VERSION 5.8 ;
BUSBITCHARS "[]" ;
DIVIDERCHAR "/" ;
UNITS
    DATABASE MICRONS 1000 ;
END UNITS

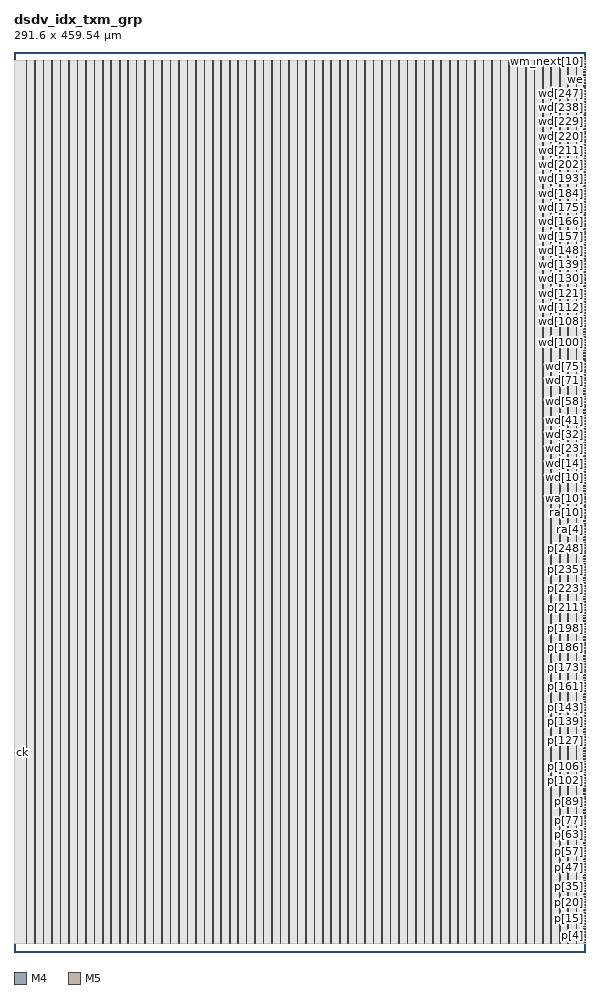
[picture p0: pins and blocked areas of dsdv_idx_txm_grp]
MACRO dsdv_idx_txm_grp
  FOREIGN dsdv_idx_txm_grp 0 0 ;
  CLASS BLOCK ;
  SIZE 291.6 BY 459.54 ;
  PIN ck
    DIRECTION INPUT ;
    USE SIGNAL ;
    PORT
      LAYER M4 ;
        RECT  0.06 102 2.408 102.024 ;
        RECT  0 102 0.084 102.024 ;
    END
  END ck
  PIN p[0]
    DIRECTION OUTPUT ;
    USE SIGNAL ;
    PORT
      LAYER M4 ;
        RECT  290.725 4.896 291.564 4.92 ;
        RECT  291.516 4.896 291.6 4.92 ;
    END
  END p[0]
  PIN p[100]
    DIRECTION OUTPUT ;
    USE SIGNAL ;
    PORT
      LAYER M4 ;
        RECT  290.725 85.968 291.564 85.992 ;
        RECT  291.516 85.968 291.6 85.992 ;
    END
  END p[100]
  PIN p[101]
    DIRECTION OUTPUT ;
    USE SIGNAL ;
    PORT
      LAYER M4 ;
        RECT  290.725 86.736 291.564 86.76 ;
        RECT  291.516 86.736 291.6 86.76 ;
    END
  END p[101]
  PIN p[102]
    DIRECTION OUTPUT ;
    USE SIGNAL ;
    PORT
      LAYER M4 ;
        RECT  290.725 87.552 291.564 87.576 ;
        RECT  291.516 87.552 291.6 87.576 ;
    END
  END p[102]
  PIN p[103]
    DIRECTION OUTPUT ;
    USE SIGNAL ;
    PORT
      LAYER M4 ;
        RECT  290.725 88.368 291.564 88.392 ;
        RECT  291.516 88.368 291.6 88.392 ;
    END
  END p[103]
  PIN p[104]
    DIRECTION OUTPUT ;
    USE SIGNAL ;
    PORT
      LAYER M4 ;
        RECT  290.725 89.184 291.564 89.208 ;
        RECT  291.516 89.184 291.6 89.208 ;
    END
  END p[104]
  PIN p[105]
    DIRECTION OUTPUT ;
    USE SIGNAL ;
    PORT
      LAYER M4 ;
        RECT  290.725 90 291.564 90.024 ;
        RECT  291.516 90 291.6 90.024 ;
    END
  END p[105]
  PIN p[106]
    DIRECTION OUTPUT ;
    USE SIGNAL ;
    PORT
      LAYER M4 ;
        RECT  290.725 90.816 291.564 90.84 ;
        RECT  291.516 90.816 291.6 90.84 ;
    END
  END p[106]
  PIN p[107]
    DIRECTION OUTPUT ;
    USE SIGNAL ;
    PORT
      LAYER M4 ;
        RECT  290.725 91.632 291.564 91.656 ;
        RECT  291.516 91.632 291.6 91.656 ;
    END
  END p[107]
  PIN p[108]
    DIRECTION OUTPUT ;
    USE SIGNAL ;
    PORT
      LAYER M4 ;
        RECT  290.725 92.448 291.564 92.472 ;
        RECT  291.516 92.448 291.6 92.472 ;
    END
  END p[108]
  PIN p[109]
    DIRECTION OUTPUT ;
    USE SIGNAL ;
    PORT
      LAYER M4 ;
        RECT  290.725 93.264 291.564 93.288 ;
        RECT  291.516 93.264 291.6 93.288 ;
    END
  END p[109]
  PIN p[10]
    DIRECTION OUTPUT ;
    USE SIGNAL ;
    PORT
      LAYER M4 ;
        RECT  290.725 13.008 291.564 13.032 ;
        RECT  291.516 13.008 291.6 13.032 ;
    END
  END p[10]
  PIN p[110]
    DIRECTION OUTPUT ;
    USE SIGNAL ;
    PORT
      LAYER M4 ;
        RECT  290.725 94.08 291.564 94.104 ;
        RECT  291.516 94.08 291.6 94.104 ;
    END
  END p[110]
  PIN p[111]
    DIRECTION OUTPUT ;
    USE SIGNAL ;
    PORT
      LAYER M4 ;
        RECT  290.725 94.848 291.564 94.872 ;
        RECT  291.516 94.848 291.6 94.872 ;
    END
  END p[111]
  PIN p[112]
    DIRECTION OUTPUT ;
    USE SIGNAL ;
    PORT
      LAYER M4 ;
        RECT  290.725 95.664 291.564 95.688 ;
        RECT  291.516 95.664 291.6 95.688 ;
    END
  END p[112]
  PIN p[113]
    DIRECTION OUTPUT ;
    USE SIGNAL ;
    PORT
      LAYER M4 ;
        RECT  290.725 96.432 291.564 96.456 ;
        RECT  291.516 96.432 291.6 96.456 ;
    END
  END p[113]
  PIN p[114]
    DIRECTION OUTPUT ;
    USE SIGNAL ;
    PORT
      LAYER M4 ;
        RECT  290.725 97.248 291.564 97.272 ;
        RECT  291.516 97.248 291.6 97.272 ;
    END
  END p[114]
  PIN p[115]
    DIRECTION OUTPUT ;
    USE SIGNAL ;
    PORT
      LAYER M4 ;
        RECT  290.725 98.064 291.564 98.088 ;
        RECT  291.516 98.064 291.6 98.088 ;
    END
  END p[115]
  PIN p[116]
    DIRECTION OUTPUT ;
    USE SIGNAL ;
    PORT
      LAYER M4 ;
        RECT  290.725 98.88 291.564 98.904 ;
        RECT  291.516 98.88 291.6 98.904 ;
    END
  END p[116]
  PIN p[117]
    DIRECTION OUTPUT ;
    USE SIGNAL ;
    PORT
      LAYER M4 ;
        RECT  290.725 99.696 291.564 99.72 ;
        RECT  291.516 99.696 291.6 99.72 ;
    END
  END p[117]
  PIN p[118]
    DIRECTION OUTPUT ;
    USE SIGNAL ;
    PORT
      LAYER M4 ;
        RECT  290.725 100.512 291.564 100.536 ;
        RECT  291.516 100.512 291.6 100.536 ;
    END
  END p[118]
  PIN p[119]
    DIRECTION OUTPUT ;
    USE SIGNAL ;
    PORT
      LAYER M4 ;
        RECT  290.725 101.328 291.564 101.352 ;
        RECT  291.516 101.328 291.6 101.352 ;
    END
  END p[119]
  PIN p[11]
    DIRECTION OUTPUT ;
    USE SIGNAL ;
    PORT
      LAYER M4 ;
        RECT  290.725 13.824 291.564 13.848 ;
        RECT  291.516 13.824 291.6 13.848 ;
    END
  END p[11]
  PIN p[120]
    DIRECTION OUTPUT ;
    USE SIGNAL ;
    PORT
      LAYER M4 ;
        RECT  290.725 102.144 291.564 102.168 ;
        RECT  291.516 102.144 291.6 102.168 ;
    END
  END p[120]
  PIN p[121]
    DIRECTION OUTPUT ;
    USE SIGNAL ;
    PORT
      LAYER M4 ;
        RECT  290.725 102.96 291.564 102.984 ;
        RECT  291.516 102.96 291.6 102.984 ;
    END
  END p[121]
  PIN p[122]
    DIRECTION OUTPUT ;
    USE SIGNAL ;
    PORT
      LAYER M4 ;
        RECT  290.725 103.776 291.564 103.8 ;
        RECT  291.516 103.776 291.6 103.8 ;
    END
  END p[122]
  PIN p[123]
    DIRECTION OUTPUT ;
    USE SIGNAL ;
    PORT
      LAYER M4 ;
        RECT  290.725 104.592 291.564 104.616 ;
        RECT  291.516 104.592 291.6 104.616 ;
    END
  END p[123]
  PIN p[124]
    DIRECTION OUTPUT ;
    USE SIGNAL ;
    PORT
      LAYER M4 ;
        RECT  290.725 105.36 291.564 105.384 ;
        RECT  291.516 105.36 291.6 105.384 ;
    END
  END p[124]
  PIN p[125]
    DIRECTION OUTPUT ;
    USE SIGNAL ;
    PORT
      LAYER M4 ;
        RECT  290.725 106.176 291.564 106.2 ;
        RECT  291.516 106.176 291.6 106.2 ;
    END
  END p[125]
  PIN p[126]
    DIRECTION OUTPUT ;
    USE SIGNAL ;
    PORT
      LAYER M4 ;
        RECT  290.725 106.992 291.564 107.016 ;
        RECT  291.516 106.992 291.6 107.016 ;
    END
  END p[126]
  PIN p[127]
    DIRECTION OUTPUT ;
    USE SIGNAL ;
    PORT
      LAYER M4 ;
        RECT  290.725 107.808 291.564 107.832 ;
        RECT  291.516 107.808 291.6 107.832 ;
    END
  END p[127]
  PIN p[128]
    DIRECTION OUTPUT ;
    USE SIGNAL ;
    PORT
      LAYER M4 ;
        RECT  290.725 108.624 291.564 108.648 ;
        RECT  291.516 108.624 291.6 108.648 ;
    END
  END p[128]
  PIN p[129]
    DIRECTION OUTPUT ;
    USE SIGNAL ;
    PORT
      LAYER M4 ;
        RECT  290.725 109.44 291.564 109.464 ;
        RECT  291.516 109.44 291.6 109.464 ;
    END
  END p[129]
  PIN p[12]
    DIRECTION OUTPUT ;
    USE SIGNAL ;
    PORT
      LAYER M4 ;
        RECT  290.725 14.64 291.564 14.664 ;
        RECT  291.516 14.64 291.6 14.664 ;
    END
  END p[12]
  PIN p[130]
    DIRECTION OUTPUT ;
    USE SIGNAL ;
    PORT
      LAYER M4 ;
        RECT  290.725 110.256 291.564 110.28 ;
        RECT  291.516 110.256 291.6 110.28 ;
    END
  END p[130]
  PIN p[131]
    DIRECTION OUTPUT ;
    USE SIGNAL ;
    PORT
      LAYER M4 ;
        RECT  290.725 111.072 291.564 111.096 ;
        RECT  291.516 111.072 291.6 111.096 ;
    END
  END p[131]
  PIN p[132]
    DIRECTION OUTPUT ;
    USE SIGNAL ;
    PORT
      LAYER M4 ;
        RECT  290.725 111.888 291.564 111.912 ;
        RECT  291.516 111.888 291.6 111.912 ;
    END
  END p[132]
  PIN p[133]
    DIRECTION OUTPUT ;
    USE SIGNAL ;
    PORT
      LAYER M4 ;
        RECT  290.725 112.704 291.564 112.728 ;
        RECT  291.516 112.704 291.6 112.728 ;
    END
  END p[133]
  PIN p[134]
    DIRECTION OUTPUT ;
    USE SIGNAL ;
    PORT
      LAYER M4 ;
        RECT  290.725 113.52 291.564 113.544 ;
        RECT  291.516 113.52 291.6 113.544 ;
    END
  END p[134]
  PIN p[135]
    DIRECTION OUTPUT ;
    USE SIGNAL ;
    PORT
      LAYER M4 ;
        RECT  290.725 114.288 291.564 114.312 ;
        RECT  291.516 114.288 291.6 114.312 ;
    END
  END p[135]
  PIN p[136]
    DIRECTION OUTPUT ;
    USE SIGNAL ;
    PORT
      LAYER M4 ;
        RECT  290.725 115.104 291.564 115.128 ;
        RECT  291.516 115.104 291.6 115.128 ;
    END
  END p[136]
  PIN p[137]
    DIRECTION OUTPUT ;
    USE SIGNAL ;
    PORT
      LAYER M4 ;
        RECT  290.725 115.92 291.564 115.944 ;
        RECT  291.516 115.92 291.6 115.944 ;
    END
  END p[137]
  PIN p[138]
    DIRECTION OUTPUT ;
    USE SIGNAL ;
    PORT
      LAYER M4 ;
        RECT  290.725 116.736 291.564 116.76 ;
        RECT  291.516 116.736 291.6 116.76 ;
    END
  END p[138]
  PIN p[139]
    DIRECTION OUTPUT ;
    USE SIGNAL ;
    PORT
      LAYER M4 ;
        RECT  290.725 117.552 291.564 117.576 ;
        RECT  291.516 117.552 291.6 117.576 ;
    END
  END p[139]
  PIN p[13]
    DIRECTION OUTPUT ;
    USE SIGNAL ;
    PORT
      LAYER M4 ;
        RECT  290.725 15.456 291.564 15.48 ;
        RECT  291.516 15.456 291.6 15.48 ;
    END
  END p[13]
  PIN p[140]
    DIRECTION OUTPUT ;
    USE SIGNAL ;
    PORT
      LAYER M4 ;
        RECT  290.725 118.368 291.564 118.392 ;
        RECT  291.516 118.368 291.6 118.392 ;
    END
  END p[140]
  PIN p[141]
    DIRECTION OUTPUT ;
    USE SIGNAL ;
    PORT
      LAYER M4 ;
        RECT  290.725 119.184 291.564 119.208 ;
        RECT  291.516 119.184 291.6 119.208 ;
    END
  END p[141]
  PIN p[142]
    DIRECTION OUTPUT ;
    USE SIGNAL ;
    PORT
      LAYER M4 ;
        RECT  290.725 120 291.564 120.024 ;
        RECT  291.516 120 291.6 120.024 ;
    END
  END p[142]
  PIN p[143]
    DIRECTION OUTPUT ;
    USE SIGNAL ;
    PORT
      LAYER M4 ;
        RECT  290.725 120.816 291.564 120.84 ;
        RECT  291.516 120.816 291.6 120.84 ;
    END
  END p[143]
  PIN p[144]
    DIRECTION OUTPUT ;
    USE SIGNAL ;
    PORT
      LAYER M4 ;
        RECT  290.725 121.632 291.564 121.656 ;
        RECT  291.516 121.632 291.6 121.656 ;
    END
  END p[144]
  PIN p[145]
    DIRECTION OUTPUT ;
    USE SIGNAL ;
    PORT
      LAYER M4 ;
        RECT  290.725 122.4 291.564 122.424 ;
        RECT  291.516 122.4 291.6 122.424 ;
    END
  END p[145]
  PIN p[146]
    DIRECTION OUTPUT ;
    USE SIGNAL ;
    PORT
      LAYER M4 ;
        RECT  290.725 123.216 291.564 123.24 ;
        RECT  291.516 123.216 291.6 123.24 ;
    END
  END p[146]
  PIN p[147]
    DIRECTION OUTPUT ;
    USE SIGNAL ;
    PORT
      LAYER M4 ;
        RECT  290.725 124.032 291.564 124.056 ;
        RECT  291.516 124.032 291.6 124.056 ;
    END
  END p[147]
  PIN p[148]
    DIRECTION OUTPUT ;
    USE SIGNAL ;
    PORT
      LAYER M4 ;
        RECT  290.725 124.8 291.564 124.824 ;
        RECT  291.516 124.8 291.6 124.824 ;
    END
  END p[148]
  PIN p[149]
    DIRECTION OUTPUT ;
    USE SIGNAL ;
    PORT
      LAYER M4 ;
        RECT  290.725 125.616 291.564 125.64 ;
        RECT  291.516 125.616 291.6 125.64 ;
    END
  END p[149]
  PIN p[14]
    DIRECTION OUTPUT ;
    USE SIGNAL ;
    PORT
      LAYER M4 ;
        RECT  290.725 16.272 291.564 16.296 ;
        RECT  291.516 16.272 291.6 16.296 ;
    END
  END p[14]
  PIN p[150]
    DIRECTION OUTPUT ;
    USE SIGNAL ;
    PORT
      LAYER M4 ;
        RECT  290.725 126.432 291.564 126.456 ;
        RECT  291.516 126.432 291.6 126.456 ;
    END
  END p[150]
  PIN p[151]
    DIRECTION OUTPUT ;
    USE SIGNAL ;
    PORT
      LAYER M4 ;
        RECT  290.725 127.248 291.564 127.272 ;
        RECT  291.516 127.248 291.6 127.272 ;
    END
  END p[151]
  PIN p[152]
    DIRECTION OUTPUT ;
    USE SIGNAL ;
    PORT
      LAYER M4 ;
        RECT  290.725 128.064 291.564 128.088 ;
        RECT  291.516 128.064 291.6 128.088 ;
    END
  END p[152]
  PIN p[153]
    DIRECTION OUTPUT ;
    USE SIGNAL ;
    PORT
      LAYER M4 ;
        RECT  290.725 128.88 291.564 128.904 ;
        RECT  291.516 128.88 291.6 128.904 ;
    END
  END p[153]
  PIN p[154]
    DIRECTION OUTPUT ;
    USE SIGNAL ;
    PORT
      LAYER M4 ;
        RECT  290.725 129.696 291.564 129.72 ;
        RECT  291.516 129.696 291.6 129.72 ;
    END
  END p[154]
  PIN p[155]
    DIRECTION OUTPUT ;
    USE SIGNAL ;
    PORT
      LAYER M4 ;
        RECT  290.725 130.512 291.564 130.536 ;
        RECT  291.516 130.512 291.6 130.536 ;
    END
  END p[155]
  PIN p[156]
    DIRECTION OUTPUT ;
    USE SIGNAL ;
    PORT
      LAYER M4 ;
        RECT  290.725 131.328 291.564 131.352 ;
        RECT  291.516 131.328 291.6 131.352 ;
    END
  END p[156]
  PIN p[157]
    DIRECTION OUTPUT ;
    USE SIGNAL ;
    PORT
      LAYER M4 ;
        RECT  290.725 132.144 291.564 132.168 ;
        RECT  291.516 132.144 291.6 132.168 ;
    END
  END p[157]
  PIN p[158]
    DIRECTION OUTPUT ;
    USE SIGNAL ;
    PORT
      LAYER M4 ;
        RECT  290.725 132.912 291.564 132.936 ;
        RECT  291.516 132.912 291.6 132.936 ;
    END
  END p[158]
  PIN p[159]
    DIRECTION OUTPUT ;
    USE SIGNAL ;
    PORT
      LAYER M4 ;
        RECT  290.725 133.728 291.564 133.752 ;
        RECT  291.516 133.728 291.6 133.752 ;
    END
  END p[159]
  PIN p[15]
    DIRECTION OUTPUT ;
    USE SIGNAL ;
    PORT
      LAYER M4 ;
        RECT  290.725 17.088 291.564 17.112 ;
        RECT  291.516 17.088 291.6 17.112 ;
    END
  END p[15]
  PIN p[160]
    DIRECTION OUTPUT ;
    USE SIGNAL ;
    PORT
      LAYER M4 ;
        RECT  290.725 134.544 291.564 134.568 ;
        RECT  291.516 134.544 291.6 134.568 ;
    END
  END p[160]
  PIN p[161]
    DIRECTION OUTPUT ;
    USE SIGNAL ;
    PORT
      LAYER M4 ;
        RECT  290.725 135.36 291.564 135.384 ;
        RECT  291.516 135.36 291.6 135.384 ;
    END
  END p[161]
  PIN p[162]
    DIRECTION OUTPUT ;
    USE SIGNAL ;
    PORT
      LAYER M4 ;
        RECT  290.725 136.176 291.564 136.2 ;
        RECT  291.516 136.176 291.6 136.2 ;
    END
  END p[162]
  PIN p[163]
    DIRECTION OUTPUT ;
    USE SIGNAL ;
    PORT
      LAYER M4 ;
        RECT  290.725 136.992 291.564 137.016 ;
        RECT  291.516 136.992 291.6 137.016 ;
    END
  END p[163]
  PIN p[164]
    DIRECTION OUTPUT ;
    USE SIGNAL ;
    PORT
      LAYER M4 ;
        RECT  290.725 137.808 291.564 137.832 ;
        RECT  291.516 137.808 291.6 137.832 ;
    END
  END p[164]
  PIN p[165]
    DIRECTION OUTPUT ;
    USE SIGNAL ;
    PORT
      LAYER M4 ;
        RECT  290.725 138.624 291.564 138.648 ;
        RECT  291.516 138.624 291.6 138.648 ;
    END
  END p[165]
  PIN p[166]
    DIRECTION OUTPUT ;
    USE SIGNAL ;
    PORT
      LAYER M4 ;
        RECT  290.725 139.44 291.564 139.464 ;
        RECT  291.516 139.44 291.6 139.464 ;
    END
  END p[166]
  PIN p[167]
    DIRECTION OUTPUT ;
    USE SIGNAL ;
    PORT
      LAYER M4 ;
        RECT  290.725 140.256 291.564 140.28 ;
        RECT  291.516 140.256 291.6 140.28 ;
    END
  END p[167]
  PIN p[168]
    DIRECTION OUTPUT ;
    USE SIGNAL ;
    PORT
      LAYER M4 ;
        RECT  290.725 141.072 291.564 141.096 ;
        RECT  291.516 141.072 291.6 141.096 ;
    END
  END p[168]
  PIN p[169]
    DIRECTION OUTPUT ;
    USE SIGNAL ;
    PORT
      LAYER M4 ;
        RECT  290.725 141.84 291.564 141.864 ;
        RECT  291.516 141.84 291.6 141.864 ;
    END
  END p[169]
  PIN p[16]
    DIRECTION OUTPUT ;
    USE SIGNAL ;
    PORT
      LAYER M4 ;
        RECT  290.725 17.904 291.564 17.928 ;
        RECT  291.516 17.904 291.6 17.928 ;
    END
  END p[16]
  PIN p[170]
    DIRECTION OUTPUT ;
    USE SIGNAL ;
    PORT
      LAYER M4 ;
        RECT  290.725 142.656 291.564 142.68 ;
        RECT  291.516 142.656 291.6 142.68 ;
    END
  END p[170]
  PIN p[171]
    DIRECTION OUTPUT ;
    USE SIGNAL ;
    PORT
      LAYER M4 ;
        RECT  290.725 143.472 291.564 143.496 ;
        RECT  291.516 143.472 291.6 143.496 ;
    END
  END p[171]
  PIN p[172]
    DIRECTION OUTPUT ;
    USE SIGNAL ;
    PORT
      LAYER M4 ;
        RECT  290.725 144.288 291.564 144.312 ;
        RECT  291.516 144.288 291.6 144.312 ;
    END
  END p[172]
  PIN p[173]
    DIRECTION OUTPUT ;
    USE SIGNAL ;
    PORT
      LAYER M4 ;
        RECT  290.725 145.104 291.564 145.128 ;
        RECT  291.516 145.104 291.6 145.128 ;
    END
  END p[173]
  PIN p[174]
    DIRECTION OUTPUT ;
    USE SIGNAL ;
    PORT
      LAYER M4 ;
        RECT  290.725 145.92 291.564 145.944 ;
        RECT  291.516 145.92 291.6 145.944 ;
    END
  END p[174]
  PIN p[175]
    DIRECTION OUTPUT ;
    USE SIGNAL ;
    PORT
      LAYER M4 ;
        RECT  290.725 146.736 291.564 146.76 ;
        RECT  291.516 146.736 291.6 146.76 ;
    END
  END p[175]
  PIN p[176]
    DIRECTION OUTPUT ;
    USE SIGNAL ;
    PORT
      LAYER M4 ;
        RECT  290.725 147.504 291.564 147.528 ;
        RECT  291.516 147.504 291.6 147.528 ;
    END
  END p[176]
  PIN p[177]
    DIRECTION OUTPUT ;
    USE SIGNAL ;
    PORT
      LAYER M4 ;
        RECT  290.725 148.32 291.564 148.344 ;
        RECT  291.516 148.32 291.6 148.344 ;
    END
  END p[177]
  PIN p[178]
    DIRECTION OUTPUT ;
    USE SIGNAL ;
    PORT
      LAYER M4 ;
        RECT  290.725 149.136 291.564 149.16 ;
        RECT  291.516 149.136 291.6 149.16 ;
    END
  END p[178]
  PIN p[179]
    DIRECTION OUTPUT ;
    USE SIGNAL ;
    PORT
      LAYER M4 ;
        RECT  290.725 149.952 291.564 149.976 ;
        RECT  291.516 149.952 291.6 149.976 ;
    END
  END p[179]
  PIN p[17]
    DIRECTION OUTPUT ;
    USE SIGNAL ;
    PORT
      LAYER M4 ;
        RECT  290.725 18.72 291.564 18.744 ;
        RECT  291.516 18.72 291.6 18.744 ;
    END
  END p[17]
  PIN p[180]
    DIRECTION OUTPUT ;
    USE SIGNAL ;
    PORT
      LAYER M4 ;
        RECT  290.725 150.768 291.564 150.792 ;
        RECT  291.516 150.768 291.6 150.792 ;
    END
  END p[180]
  PIN p[181]
    DIRECTION OUTPUT ;
    USE SIGNAL ;
    PORT
      LAYER M4 ;
        RECT  290.725 151.584 291.564 151.608 ;
        RECT  291.516 151.584 291.6 151.608 ;
    END
  END p[181]
  PIN p[182]
    DIRECTION OUTPUT ;
    USE SIGNAL ;
    PORT
      LAYER M4 ;
        RECT  290.725 152.352 291.564 152.376 ;
        RECT  291.516 152.352 291.6 152.376 ;
    END
  END p[182]
  PIN p[183]
    DIRECTION OUTPUT ;
    USE SIGNAL ;
    PORT
      LAYER M4 ;
        RECT  290.725 153.168 291.564 153.192 ;
        RECT  291.516 153.168 291.6 153.192 ;
    END
  END p[183]
  PIN p[184]
    DIRECTION OUTPUT ;
    USE SIGNAL ;
    PORT
      LAYER M4 ;
        RECT  290.725 153.984 291.564 154.008 ;
        RECT  291.516 153.984 291.6 154.008 ;
    END
  END p[184]
  PIN p[185]
    DIRECTION OUTPUT ;
    USE SIGNAL ;
    PORT
      LAYER M4 ;
        RECT  290.725 154.8 291.564 154.824 ;
        RECT  291.516 154.8 291.6 154.824 ;
    END
  END p[185]
  PIN p[186]
    DIRECTION OUTPUT ;
    USE SIGNAL ;
    PORT
      LAYER M4 ;
        RECT  290.725 155.616 291.564 155.64 ;
        RECT  291.516 155.616 291.6 155.64 ;
    END
  END p[186]
  PIN p[187]
    DIRECTION OUTPUT ;
    USE SIGNAL ;
    PORT
      LAYER M4 ;
        RECT  290.725 156.432 291.564 156.456 ;
        RECT  291.516 156.432 291.6 156.456 ;
    END
  END p[187]
  PIN p[188]
    DIRECTION OUTPUT ;
    USE SIGNAL ;
    PORT
      LAYER M4 ;
        RECT  290.725 157.248 291.564 157.272 ;
        RECT  291.516 157.248 291.6 157.272 ;
    END
  END p[188]
  PIN p[189]
    DIRECTION OUTPUT ;
    USE SIGNAL ;
    PORT
      LAYER M4 ;
        RECT  290.725 158.064 291.564 158.088 ;
        RECT  291.516 158.064 291.6 158.088 ;
    END
  END p[189]
  PIN p[18]
    DIRECTION OUTPUT ;
    USE SIGNAL ;
    PORT
      LAYER M4 ;
        RECT  290.725 19.536 291.564 19.56 ;
        RECT  291.516 19.536 291.6 19.56 ;
    END
  END p[18]
  PIN p[190]
    DIRECTION OUTPUT ;
    USE SIGNAL ;
    PORT
      LAYER M4 ;
        RECT  290.725 158.88 291.564 158.904 ;
        RECT  291.516 158.88 291.6 158.904 ;
    END
  END p[190]
  PIN p[191]
    DIRECTION OUTPUT ;
    USE SIGNAL ;
    PORT
      LAYER M4 ;
        RECT  290.725 159.696 291.564 159.72 ;
        RECT  291.516 159.696 291.6 159.72 ;
    END
  END p[191]
  PIN p[192]
    DIRECTION OUTPUT ;
    USE SIGNAL ;
    PORT
      LAYER M4 ;
        RECT  290.725 160.512 291.564 160.536 ;
        RECT  291.516 160.512 291.6 160.536 ;
    END
  END p[192]
  PIN p[193]
    DIRECTION OUTPUT ;
    USE SIGNAL ;
    PORT
      LAYER M4 ;
        RECT  290.725 161.28 291.564 161.304 ;
        RECT  291.516 161.28 291.6 161.304 ;
    END
  END p[193]
  PIN p[194]
    DIRECTION OUTPUT ;
    USE SIGNAL ;
    PORT
      LAYER M4 ;
        RECT  290.725 162.096 291.564 162.12 ;
        RECT  291.516 162.096 291.6 162.12 ;
    END
  END p[194]
  PIN p[195]
    DIRECTION OUTPUT ;
    USE SIGNAL ;
    PORT
      LAYER M4 ;
        RECT  290.725 162.912 291.564 162.936 ;
        RECT  291.516 162.912 291.6 162.936 ;
    END
  END p[195]
  PIN p[196]
    DIRECTION OUTPUT ;
    USE SIGNAL ;
    PORT
      LAYER M4 ;
        RECT  290.725 163.728 291.564 163.752 ;
        RECT  291.516 163.728 291.6 163.752 ;
    END
  END p[196]
  PIN p[197]
    DIRECTION OUTPUT ;
    USE SIGNAL ;
    PORT
      LAYER M4 ;
        RECT  290.725 164.544 291.564 164.568 ;
        RECT  291.516 164.544 291.6 164.568 ;
    END
  END p[197]
  PIN p[198]
    DIRECTION OUTPUT ;
    USE SIGNAL ;
    PORT
      LAYER M4 ;
        RECT  290.725 165.36 291.564 165.384 ;
        RECT  291.516 165.36 291.6 165.384 ;
    END
  END p[198]
  PIN p[199]
    DIRECTION OUTPUT ;
    USE SIGNAL ;
    PORT
      LAYER M4 ;
        RECT  290.725 166.176 291.564 166.2 ;
        RECT  291.516 166.176 291.6 166.2 ;
    END
  END p[199]
  PIN p[19]
    DIRECTION OUTPUT ;
    USE SIGNAL ;
    PORT
      LAYER M4 ;
        RECT  290.725 20.304 291.564 20.328 ;
        RECT  291.516 20.304 291.6 20.328 ;
    END
  END p[19]
  PIN p[1]
    DIRECTION OUTPUT ;
    USE SIGNAL ;
    PORT
      LAYER M4 ;
        RECT  290.725 5.712 291.564 5.736 ;
        RECT  291.516 5.712 291.6 5.736 ;
    END
  END p[1]
  PIN p[200]
    DIRECTION OUTPUT ;
    USE SIGNAL ;
    PORT
      LAYER M4 ;
        RECT  290.725 166.992 291.564 167.016 ;
        RECT  291.516 166.992 291.6 167.016 ;
    END
  END p[200]
  PIN p[201]
    DIRECTION OUTPUT ;
    USE SIGNAL ;
    PORT
      LAYER M4 ;
        RECT  290.725 167.808 291.564 167.832 ;
        RECT  291.516 167.808 291.6 167.832 ;
    END
  END p[201]
  PIN p[202]
    DIRECTION OUTPUT ;
    USE SIGNAL ;
    PORT
      LAYER M4 ;
        RECT  290.725 168.624 291.564 168.648 ;
        RECT  291.516 168.624 291.6 168.648 ;
    END
  END p[202]
  PIN p[203]
    DIRECTION OUTPUT ;
    USE SIGNAL ;
    PORT
      LAYER M4 ;
        RECT  290.725 169.392 291.564 169.416 ;
        RECT  291.516 169.392 291.6 169.416 ;
    END
  END p[203]
  PIN p[204]
    DIRECTION OUTPUT ;
    USE SIGNAL ;
    PORT
      LAYER M4 ;
        RECT  290.725 170.208 291.564 170.232 ;
        RECT  291.516 170.208 291.6 170.232 ;
    END
  END p[204]
  PIN p[205]
    DIRECTION OUTPUT ;
    USE SIGNAL ;
    PORT
      LAYER M4 ;
        RECT  290.725 171.024 291.564 171.048 ;
        RECT  291.516 171.024 291.6 171.048 ;
    END
  END p[205]
  PIN p[206]
    DIRECTION OUTPUT ;
    USE SIGNAL ;
    PORT
      LAYER M4 ;
        RECT  290.725 171.84 291.564 171.864 ;
        RECT  291.516 171.84 291.6 171.864 ;
    END
  END p[206]
  PIN p[207]
    DIRECTION OUTPUT ;
    USE SIGNAL ;
    PORT
      LAYER M4 ;
        RECT  290.725 172.656 291.564 172.68 ;
        RECT  291.516 172.656 291.6 172.68 ;
    END
  END p[207]
  PIN p[208]
    DIRECTION OUTPUT ;
    USE SIGNAL ;
    PORT
      LAYER M4 ;
        RECT  290.725 173.424 291.564 173.448 ;
        RECT  291.516 173.424 291.6 173.448 ;
    END
  END p[208]
  PIN p[209]
    DIRECTION OUTPUT ;
    USE SIGNAL ;
    PORT
      LAYER M4 ;
        RECT  290.725 174.24 291.564 174.264 ;
        RECT  291.516 174.24 291.6 174.264 ;
    END
  END p[209]
  PIN p[20]
    DIRECTION OUTPUT ;
    USE SIGNAL ;
    PORT
      LAYER M4 ;
        RECT  290.725 21.12 291.564 21.144 ;
        RECT  291.516 21.12 291.6 21.144 ;
    END
  END p[20]
  PIN p[210]
    DIRECTION OUTPUT ;
    USE SIGNAL ;
    PORT
      LAYER M4 ;
        RECT  290.725 175.056 291.564 175.08 ;
        RECT  291.516 175.056 291.6 175.08 ;
    END
  END p[210]
  PIN p[211]
    DIRECTION OUTPUT ;
    USE SIGNAL ;
    PORT
      LAYER M4 ;
        RECT  290.725 175.872 291.564 175.896 ;
        RECT  291.516 175.872 291.6 175.896 ;
    END
  END p[211]
  PIN p[212]
    DIRECTION OUTPUT ;
    USE SIGNAL ;
    PORT
      LAYER M4 ;
        RECT  290.725 176.688 291.564 176.712 ;
        RECT  291.516 176.688 291.6 176.712 ;
    END
  END p[212]
  PIN p[213]
    DIRECTION OUTPUT ;
    USE SIGNAL ;
    PORT
      LAYER M4 ;
        RECT  290.725 177.504 291.564 177.528 ;
        RECT  291.516 177.504 291.6 177.528 ;
    END
  END p[213]
  PIN p[214]
    DIRECTION OUTPUT ;
    USE SIGNAL ;
    PORT
      LAYER M4 ;
        RECT  290.725 178.32 291.564 178.344 ;
        RECT  291.516 178.32 291.6 178.344 ;
    END
  END p[214]
  PIN p[215]
    DIRECTION OUTPUT ;
    USE SIGNAL ;
    PORT
      LAYER M4 ;
        RECT  290.725 179.136 291.564 179.16 ;
        RECT  291.516 179.136 291.6 179.16 ;
    END
  END p[215]
  PIN p[216]
    DIRECTION OUTPUT ;
    USE SIGNAL ;
    PORT
      LAYER M4 ;
        RECT  290.725 179.904 291.564 179.928 ;
        RECT  291.516 179.904 291.6 179.928 ;
    END
  END p[216]
  PIN p[217]
    DIRECTION OUTPUT ;
    USE SIGNAL ;
    PORT
      LAYER M4 ;
        RECT  290.725 180.72 291.564 180.744 ;
        RECT  291.516 180.72 291.6 180.744 ;
    END
  END p[217]
  PIN p[218]
    DIRECTION OUTPUT ;
    USE SIGNAL ;
    PORT
      LAYER M4 ;
        RECT  290.725 181.536 291.564 181.56 ;
        RECT  291.516 181.536 291.6 181.56 ;
    END
  END p[218]
  PIN p[219]
    DIRECTION OUTPUT ;
    USE SIGNAL ;
    PORT
      LAYER M4 ;
        RECT  290.725 182.352 291.564 182.376 ;
        RECT  291.516 182.352 291.6 182.376 ;
    END
  END p[219]
  PIN p[21]
    DIRECTION OUTPUT ;
    USE SIGNAL ;
    PORT
      LAYER M4 ;
        RECT  290.725 21.888 291.564 21.912 ;
        RECT  291.516 21.888 291.6 21.912 ;
    END
  END p[21]
  PIN p[220]
    DIRECTION OUTPUT ;
    USE SIGNAL ;
    PORT
      LAYER M4 ;
        RECT  290.725 183.168 291.564 183.192 ;
        RECT  291.516 183.168 291.6 183.192 ;
    END
  END p[220]
  PIN p[221]
    DIRECTION OUTPUT ;
    USE SIGNAL ;
    PORT
      LAYER M4 ;
        RECT  290.725 183.984 291.564 184.008 ;
        RECT  291.516 183.984 291.6 184.008 ;
    END
  END p[221]
  PIN p[222]
    DIRECTION OUTPUT ;
    USE SIGNAL ;
    PORT
      LAYER M4 ;
        RECT  290.725 184.8 291.564 184.824 ;
        RECT  291.516 184.8 291.6 184.824 ;
    END
  END p[222]
  PIN p[223]
    DIRECTION OUTPUT ;
    USE SIGNAL ;
    PORT
      LAYER M4 ;
        RECT  290.725 185.616 291.564 185.64 ;
        RECT  291.516 185.616 291.6 185.64 ;
    END
  END p[223]
  PIN p[224]
    DIRECTION OUTPUT ;
    USE SIGNAL ;
    PORT
      LAYER M4 ;
        RECT  290.725 186.432 291.564 186.456 ;
        RECT  291.516 186.432 291.6 186.456 ;
    END
  END p[224]
  PIN p[225]
    DIRECTION OUTPUT ;
    USE SIGNAL ;
    PORT
      LAYER M4 ;
        RECT  290.725 187.248 291.564 187.272 ;
        RECT  291.516 187.248 291.6 187.272 ;
    END
  END p[225]
  PIN p[226]
    DIRECTION OUTPUT ;
    USE SIGNAL ;
    PORT
      LAYER M4 ;
        RECT  290.725 188.064 291.564 188.088 ;
        RECT  291.516 188.064 291.6 188.088 ;
    END
  END p[226]
  PIN p[227]
    DIRECTION OUTPUT ;
    USE SIGNAL ;
    PORT
      LAYER M4 ;
        RECT  290.725 188.832 291.564 188.856 ;
        RECT  291.516 188.832 291.6 188.856 ;
    END
  END p[227]
  PIN p[228]
    DIRECTION OUTPUT ;
    USE SIGNAL ;
    PORT
      LAYER M4 ;
        RECT  290.725 189.648 291.564 189.672 ;
        RECT  291.516 189.648 291.6 189.672 ;
    END
  END p[228]
  PIN p[229]
    DIRECTION OUTPUT ;
    USE SIGNAL ;
    PORT
      LAYER M4 ;
        RECT  290.725 190.464 291.564 190.488 ;
        RECT  291.516 190.464 291.6 190.488 ;
    END
  END p[229]
  PIN p[22]
    DIRECTION OUTPUT ;
    USE SIGNAL ;
    PORT
      LAYER M4 ;
        RECT  290.725 22.704 291.564 22.728 ;
        RECT  291.516 22.704 291.6 22.728 ;
    END
  END p[22]
  PIN p[230]
    DIRECTION OUTPUT ;
    USE SIGNAL ;
    PORT
      LAYER M4 ;
        RECT  290.725 191.28 291.564 191.304 ;
        RECT  291.516 191.28 291.6 191.304 ;
    END
  END p[230]
  PIN p[231]
    DIRECTION OUTPUT ;
    USE SIGNAL ;
    PORT
      LAYER M4 ;
        RECT  290.725 192.096 291.564 192.12 ;
        RECT  291.516 192.096 291.6 192.12 ;
    END
  END p[231]
  PIN p[232]
    DIRECTION OUTPUT ;
    USE SIGNAL ;
    PORT
      LAYER M4 ;
        RECT  290.725 192.912 291.564 192.936 ;
        RECT  291.516 192.912 291.6 192.936 ;
    END
  END p[232]
  PIN p[233]
    DIRECTION OUTPUT ;
    USE SIGNAL ;
    PORT
      LAYER M4 ;
        RECT  290.725 193.728 291.564 193.752 ;
        RECT  291.516 193.728 291.6 193.752 ;
    END
  END p[233]
  PIN p[234]
    DIRECTION OUTPUT ;
    USE SIGNAL ;
    PORT
      LAYER M4 ;
        RECT  290.725 194.544 291.564 194.568 ;
        RECT  291.516 194.544 291.6 194.568 ;
    END
  END p[234]
  PIN p[235]
    DIRECTION OUTPUT ;
    USE SIGNAL ;
    PORT
      LAYER M4 ;
        RECT  290.725 195.36 291.564 195.384 ;
        RECT  291.516 195.36 291.6 195.384 ;
    END
  END p[235]
  PIN p[236]
    DIRECTION OUTPUT ;
    USE SIGNAL ;
    PORT
      LAYER M4 ;
        RECT  290.725 196.176 291.564 196.2 ;
        RECT  291.516 196.176 291.6 196.2 ;
    END
  END p[236]
  PIN p[237]
    DIRECTION OUTPUT ;
    USE SIGNAL ;
    PORT
      LAYER M4 ;
        RECT  290.725 196.992 291.564 197.016 ;
        RECT  291.516 196.992 291.6 197.016 ;
    END
  END p[237]
  PIN p[238]
    DIRECTION OUTPUT ;
    USE SIGNAL ;
    PORT
      LAYER M4 ;
        RECT  290.725 197.76 291.564 197.784 ;
        RECT  291.516 197.76 291.6 197.784 ;
    END
  END p[238]
  PIN p[239]
    DIRECTION OUTPUT ;
    USE SIGNAL ;
    PORT
      LAYER M4 ;
        RECT  290.725 198.576 291.564 198.6 ;
        RECT  291.516 198.576 291.6 198.6 ;
    END
  END p[239]
  PIN p[23]
    DIRECTION OUTPUT ;
    USE SIGNAL ;
    PORT
      LAYER M4 ;
        RECT  290.725 23.52 291.564 23.544 ;
        RECT  291.516 23.52 291.6 23.544 ;
    END
  END p[23]
  PIN p[240]
    DIRECTION OUTPUT ;
    USE SIGNAL ;
    PORT
      LAYER M4 ;
        RECT  290.725 199.344 291.564 199.368 ;
        RECT  291.516 199.344 291.6 199.368 ;
    END
  END p[240]
  PIN p[241]
    DIRECTION OUTPUT ;
    USE SIGNAL ;
    PORT
      LAYER M4 ;
        RECT  290.725 200.16 291.564 200.184 ;
        RECT  291.516 200.16 291.6 200.184 ;
    END
  END p[241]
  PIN p[242]
    DIRECTION OUTPUT ;
    USE SIGNAL ;
    PORT
      LAYER M4 ;
        RECT  290.725 200.976 291.564 201 ;
        RECT  291.516 200.976 291.6 201 ;
    END
  END p[242]
  PIN p[243]
    DIRECTION OUTPUT ;
    USE SIGNAL ;
    PORT
      LAYER M4 ;
        RECT  290.725 201.792 291.564 201.816 ;
        RECT  291.516 201.792 291.6 201.816 ;
    END
  END p[243]
  PIN p[244]
    DIRECTION OUTPUT ;
    USE SIGNAL ;
    PORT
      LAYER M4 ;
        RECT  290.725 202.608 291.564 202.632 ;
        RECT  291.516 202.608 291.6 202.632 ;
    END
  END p[244]
  PIN p[245]
    DIRECTION OUTPUT ;
    USE SIGNAL ;
    PORT
      LAYER M4 ;
        RECT  290.725 203.424 291.564 203.448 ;
        RECT  291.516 203.424 291.6 203.448 ;
    END
  END p[245]
  PIN p[246]
    DIRECTION OUTPUT ;
    USE SIGNAL ;
    PORT
      LAYER M4 ;
        RECT  290.725 204.24 291.564 204.264 ;
        RECT  291.516 204.24 291.6 204.264 ;
    END
  END p[246]
  PIN p[247]
    DIRECTION OUTPUT ;
    USE SIGNAL ;
    PORT
      LAYER M4 ;
        RECT  290.725 205.056 291.564 205.08 ;
        RECT  291.516 205.056 291.6 205.08 ;
    END
  END p[247]
  PIN p[248]
    DIRECTION OUTPUT ;
    USE SIGNAL ;
    PORT
      LAYER M4 ;
        RECT  290.725 205.872 291.564 205.896 ;
        RECT  291.516 205.872 291.6 205.896 ;
    END
  END p[248]
  PIN p[249]
    DIRECTION OUTPUT ;
    USE SIGNAL ;
    PORT
      LAYER M4 ;
        RECT  290.725 206.688 291.564 206.712 ;
        RECT  291.516 206.688 291.6 206.712 ;
    END
  END p[249]
  PIN p[24]
    DIRECTION OUTPUT ;
    USE SIGNAL ;
    PORT
      LAYER M4 ;
        RECT  290.725 24.336 291.564 24.36 ;
        RECT  291.516 24.336 291.6 24.36 ;
    END
  END p[24]
  PIN p[250]
    DIRECTION OUTPUT ;
    USE SIGNAL ;
    PORT
      LAYER M4 ;
        RECT  290.725 207.456 291.564 207.48 ;
        RECT  291.516 207.456 291.6 207.48 ;
    END
  END p[250]
  PIN p[251]
    DIRECTION OUTPUT ;
    USE SIGNAL ;
    PORT
      LAYER M4 ;
        RECT  290.725 208.272 291.564 208.296 ;
        RECT  291.516 208.272 291.6 208.296 ;
    END
  END p[251]
  PIN p[252]
    DIRECTION OUTPUT ;
    USE SIGNAL ;
    PORT
      LAYER M4 ;
        RECT  290.725 209.088 291.564 209.112 ;
        RECT  291.516 209.088 291.6 209.112 ;
    END
  END p[252]
  PIN p[253]
    DIRECTION OUTPUT ;
    USE SIGNAL ;
    PORT
      LAYER M4 ;
        RECT  290.725 209.904 291.564 209.928 ;
        RECT  291.516 209.904 291.6 209.928 ;
    END
  END p[253]
  PIN p[254]
    DIRECTION OUTPUT ;
    USE SIGNAL ;
    PORT
      LAYER M4 ;
        RECT  290.725 210.72 291.564 210.744 ;
        RECT  291.516 210.72 291.6 210.744 ;
    END
  END p[254]
  PIN p[255]
    DIRECTION OUTPUT ;
    USE SIGNAL ;
    PORT
      LAYER M4 ;
        RECT  290.725 211.536 291.564 211.56 ;
        RECT  291.516 211.536 291.6 211.56 ;
    END
  END p[255]
  PIN p[25]
    DIRECTION OUTPUT ;
    USE SIGNAL ;
    PORT
      LAYER M4 ;
        RECT  290.725 25.152 291.564 25.176 ;
        RECT  291.516 25.152 291.6 25.176 ;
    END
  END p[25]
  PIN p[26]
    DIRECTION OUTPUT ;
    USE SIGNAL ;
    PORT
      LAYER M4 ;
        RECT  290.725 25.968 291.564 25.992 ;
        RECT  291.516 25.968 291.6 25.992 ;
    END
  END p[26]
  PIN p[27]
    DIRECTION OUTPUT ;
    USE SIGNAL ;
    PORT
      LAYER M4 ;
        RECT  290.725 26.784 291.564 26.808 ;
        RECT  291.516 26.784 291.6 26.808 ;
    END
  END p[27]
  PIN p[28]
    DIRECTION OUTPUT ;
    USE SIGNAL ;
    PORT
      LAYER M4 ;
        RECT  290.725 27.6 291.564 27.624 ;
        RECT  291.516 27.6 291.6 27.624 ;
    END
  END p[28]
  PIN p[29]
    DIRECTION OUTPUT ;
    USE SIGNAL ;
    PORT
      LAYER M4 ;
        RECT  290.725 28.416 291.564 28.44 ;
        RECT  291.516 28.416 291.6 28.44 ;
    END
  END p[29]
  PIN p[2]
    DIRECTION OUTPUT ;
    USE SIGNAL ;
    PORT
      LAYER M4 ;
        RECT  290.725 6.528 291.564 6.552 ;
        RECT  291.516 6.528 291.6 6.552 ;
    END
  END p[2]
  PIN p[30]
    DIRECTION OUTPUT ;
    USE SIGNAL ;
    PORT
      LAYER M4 ;
        RECT  290.725 29.232 291.564 29.256 ;
        RECT  291.516 29.232 291.6 29.256 ;
    END
  END p[30]
  PIN p[31]
    DIRECTION OUTPUT ;
    USE SIGNAL ;
    PORT
      LAYER M4 ;
        RECT  290.725 30.048 291.564 30.072 ;
        RECT  291.516 30.048 291.6 30.072 ;
    END
  END p[31]
  PIN p[32]
    DIRECTION OUTPUT ;
    USE SIGNAL ;
    PORT
      LAYER M4 ;
        RECT  290.725 30.816 291.564 30.84 ;
        RECT  291.516 30.816 291.6 30.84 ;
    END
  END p[32]
  PIN p[33]
    DIRECTION OUTPUT ;
    USE SIGNAL ;
    PORT
      LAYER M4 ;
        RECT  290.725 31.632 291.564 31.656 ;
        RECT  291.516 31.632 291.6 31.656 ;
    END
  END p[33]
  PIN p[34]
    DIRECTION OUTPUT ;
    USE SIGNAL ;
    PORT
      LAYER M4 ;
        RECT  290.725 32.448 291.564 32.472 ;
        RECT  291.516 32.448 291.6 32.472 ;
    END
  END p[34]
  PIN p[35]
    DIRECTION OUTPUT ;
    USE SIGNAL ;
    PORT
      LAYER M4 ;
        RECT  290.725 33.264 291.564 33.288 ;
        RECT  291.516 33.264 291.6 33.288 ;
    END
  END p[35]
  PIN p[36]
    DIRECTION OUTPUT ;
    USE SIGNAL ;
    PORT
      LAYER M4 ;
        RECT  290.725 34.08 291.564 34.104 ;
        RECT  291.516 34.08 291.6 34.104 ;
    END
  END p[36]
  PIN p[37]
    DIRECTION OUTPUT ;
    USE SIGNAL ;
    PORT
      LAYER M4 ;
        RECT  290.725 34.896 291.564 34.92 ;
        RECT  291.516 34.896 291.6 34.92 ;
    END
  END p[37]
  PIN p[38]
    DIRECTION OUTPUT ;
    USE SIGNAL ;
    PORT
      LAYER M4 ;
        RECT  290.725 35.712 291.564 35.736 ;
        RECT  291.516 35.712 291.6 35.736 ;
    END
  END p[38]
  PIN p[39]
    DIRECTION OUTPUT ;
    USE SIGNAL ;
    PORT
      LAYER M4 ;
        RECT  290.725 36.528 291.564 36.552 ;
        RECT  291.516 36.528 291.6 36.552 ;
    END
  END p[39]
  PIN p[3]
    DIRECTION OUTPUT ;
    USE SIGNAL ;
    PORT
      LAYER M4 ;
        RECT  290.725 7.344 291.564 7.368 ;
        RECT  291.516 7.344 291.6 7.368 ;
    END
  END p[3]
  PIN p[40]
    DIRECTION OUTPUT ;
    USE SIGNAL ;
    PORT
      LAYER M4 ;
        RECT  290.725 37.344 291.564 37.368 ;
        RECT  291.516 37.344 291.6 37.368 ;
    END
  END p[40]
  PIN p[41]
    DIRECTION OUTPUT ;
    USE SIGNAL ;
    PORT
      LAYER M4 ;
        RECT  290.725 38.16 291.564 38.184 ;
        RECT  291.516 38.16 291.6 38.184 ;
    END
  END p[41]
  PIN p[42]
    DIRECTION OUTPUT ;
    USE SIGNAL ;
    PORT
      LAYER M4 ;
        RECT  290.725 38.976 291.564 39 ;
        RECT  291.516 38.976 291.6 39 ;
    END
  END p[42]
  PIN p[43]
    DIRECTION OUTPUT ;
    USE SIGNAL ;
    PORT
      LAYER M4 ;
        RECT  290.725 39.744 291.564 39.768 ;
        RECT  291.516 39.744 291.6 39.768 ;
    END
  END p[43]
  PIN p[44]
    DIRECTION OUTPUT ;
    USE SIGNAL ;
    PORT
      LAYER M4 ;
        RECT  290.725 40.56 291.564 40.584 ;
        RECT  291.516 40.56 291.6 40.584 ;
    END
  END p[44]
  PIN p[45]
    DIRECTION OUTPUT ;
    USE SIGNAL ;
    PORT
      LAYER M4 ;
        RECT  290.725 41.376 291.564 41.4 ;
        RECT  291.516 41.376 291.6 41.4 ;
    END
  END p[45]
  PIN p[46]
    DIRECTION OUTPUT ;
    USE SIGNAL ;
    PORT
      LAYER M4 ;
        RECT  290.725 42.192 291.564 42.216 ;
        RECT  291.516 42.192 291.6 42.216 ;
    END
  END p[46]
  PIN p[47]
    DIRECTION OUTPUT ;
    USE SIGNAL ;
    PORT
      LAYER M4 ;
        RECT  290.725 43.008 291.564 43.032 ;
        RECT  291.516 43.008 291.6 43.032 ;
    END
  END p[47]
  PIN p[48]
    DIRECTION OUTPUT ;
    USE SIGNAL ;
    PORT
      LAYER M4 ;
        RECT  290.725 43.824 291.564 43.848 ;
        RECT  291.516 43.824 291.6 43.848 ;
    END
  END p[48]
  PIN p[49]
    DIRECTION OUTPUT ;
    USE SIGNAL ;
    PORT
      LAYER M4 ;
        RECT  290.725 44.64 291.564 44.664 ;
        RECT  291.516 44.64 291.6 44.664 ;
    END
  END p[49]
  PIN p[4]
    DIRECTION OUTPUT ;
    USE SIGNAL ;
    PORT
      LAYER M4 ;
        RECT  290.725 8.16 291.564 8.184 ;
        RECT  291.516 8.16 291.6 8.184 ;
    END
  END p[4]
  PIN p[50]
    DIRECTION OUTPUT ;
    USE SIGNAL ;
    PORT
      LAYER M4 ;
        RECT  290.725 45.408 291.564 45.432 ;
        RECT  291.516 45.408 291.6 45.432 ;
    END
  END p[50]
  PIN p[51]
    DIRECTION OUTPUT ;
    USE SIGNAL ;
    PORT
      LAYER M4 ;
        RECT  290.725 46.224 291.564 46.248 ;
        RECT  291.516 46.224 291.6 46.248 ;
    END
  END p[51]
  PIN p[52]
    DIRECTION OUTPUT ;
    USE SIGNAL ;
    PORT
      LAYER M4 ;
        RECT  290.725 47.04 291.564 47.064 ;
        RECT  291.516 47.04 291.6 47.064 ;
    END
  END p[52]
  PIN p[53]
    DIRECTION OUTPUT ;
    USE SIGNAL ;
    PORT
      LAYER M4 ;
        RECT  290.725 47.856 291.564 47.88 ;
        RECT  291.516 47.856 291.6 47.88 ;
    END
  END p[53]
  PIN p[54]
    DIRECTION OUTPUT ;
    USE SIGNAL ;
    PORT
      LAYER M4 ;
        RECT  290.725 48.672 291.564 48.696 ;
        RECT  291.516 48.672 291.6 48.696 ;
    END
  END p[54]
  PIN p[55]
    DIRECTION OUTPUT ;
    USE SIGNAL ;
    PORT
      LAYER M4 ;
        RECT  290.725 49.488 291.564 49.512 ;
        RECT  291.516 49.488 291.6 49.512 ;
    END
  END p[55]
  PIN p[56]
    DIRECTION OUTPUT ;
    USE SIGNAL ;
    PORT
      LAYER M4 ;
        RECT  290.725 50.256 291.564 50.28 ;
        RECT  291.516 50.256 291.6 50.28 ;
    END
  END p[56]
  PIN p[57]
    DIRECTION OUTPUT ;
    USE SIGNAL ;
    PORT
      LAYER M4 ;
        RECT  290.725 51.072 291.564 51.096 ;
        RECT  291.516 51.072 291.6 51.096 ;
    END
  END p[57]
  PIN p[58]
    DIRECTION OUTPUT ;
    USE SIGNAL ;
    PORT
      LAYER M4 ;
        RECT  290.725 51.888 291.564 51.912 ;
        RECT  291.516 51.888 291.6 51.912 ;
    END
  END p[58]
  PIN p[59]
    DIRECTION OUTPUT ;
    USE SIGNAL ;
    PORT
      LAYER M4 ;
        RECT  290.725 52.704 291.564 52.728 ;
        RECT  291.516 52.704 291.6 52.728 ;
    END
  END p[59]
  PIN p[5]
    DIRECTION OUTPUT ;
    USE SIGNAL ;
    PORT
      LAYER M4 ;
        RECT  290.725 8.976 291.564 9 ;
        RECT  291.516 8.976 291.6 9 ;
    END
  END p[5]
  PIN p[60]
    DIRECTION OUTPUT ;
    USE SIGNAL ;
    PORT
      LAYER M4 ;
        RECT  290.725 53.52 291.564 53.544 ;
        RECT  291.516 53.52 291.6 53.544 ;
    END
  END p[60]
  PIN p[61]
    DIRECTION OUTPUT ;
    USE SIGNAL ;
    PORT
      LAYER M4 ;
        RECT  290.725 54.336 291.564 54.36 ;
        RECT  291.516 54.336 291.6 54.36 ;
    END
  END p[61]
  PIN p[62]
    DIRECTION OUTPUT ;
    USE SIGNAL ;
    PORT
      LAYER M4 ;
        RECT  290.725 55.152 291.564 55.176 ;
        RECT  291.516 55.152 291.6 55.176 ;
    END
  END p[62]
  PIN p[63]
    DIRECTION OUTPUT ;
    USE SIGNAL ;
    PORT
      LAYER M4 ;
        RECT  290.725 55.968 291.564 55.992 ;
        RECT  291.516 55.968 291.6 55.992 ;
    END
  END p[63]
  PIN p[64]
    DIRECTION OUTPUT ;
    USE SIGNAL ;
    PORT
      LAYER M4 ;
        RECT  290.725 56.784 291.564 56.808 ;
        RECT  291.516 56.784 291.6 56.808 ;
    END
  END p[64]
  PIN p[65]
    DIRECTION OUTPUT ;
    USE SIGNAL ;
    PORT
      LAYER M4 ;
        RECT  290.725 57.6 291.564 57.624 ;
        RECT  291.516 57.6 291.6 57.624 ;
    END
  END p[65]
  PIN p[66]
    DIRECTION OUTPUT ;
    USE SIGNAL ;
    PORT
      LAYER M4 ;
        RECT  290.725 58.368 291.564 58.392 ;
        RECT  291.516 58.368 291.6 58.392 ;
    END
  END p[66]
  PIN p[67]
    DIRECTION OUTPUT ;
    USE SIGNAL ;
    PORT
      LAYER M4 ;
        RECT  290.725 59.184 291.564 59.208 ;
        RECT  291.516 59.184 291.6 59.208 ;
    END
  END p[67]
  PIN p[68]
    DIRECTION OUTPUT ;
    USE SIGNAL ;
    PORT
      LAYER M4 ;
        RECT  290.725 60 291.564 60.024 ;
        RECT  291.516 60 291.6 60.024 ;
    END
  END p[68]
  PIN p[69]
    DIRECTION OUTPUT ;
    USE SIGNAL ;
    PORT
      LAYER M4 ;
        RECT  290.725 60.816 291.564 60.84 ;
        RECT  291.516 60.816 291.6 60.84 ;
    END
  END p[69]
  PIN p[6]
    DIRECTION OUTPUT ;
    USE SIGNAL ;
    PORT
      LAYER M4 ;
        RECT  290.725 9.792 291.564 9.816 ;
        RECT  291.516 9.792 291.6 9.816 ;
    END
  END p[6]
  PIN p[70]
    DIRECTION OUTPUT ;
    USE SIGNAL ;
    PORT
      LAYER M4 ;
        RECT  290.725 61.632 291.564 61.656 ;
        RECT  291.516 61.632 291.6 61.656 ;
    END
  END p[70]
  PIN p[71]
    DIRECTION OUTPUT ;
    USE SIGNAL ;
    PORT
      LAYER M4 ;
        RECT  290.725 62.448 291.564 62.472 ;
        RECT  291.516 62.448 291.6 62.472 ;
    END
  END p[71]
  PIN p[72]
    DIRECTION OUTPUT ;
    USE SIGNAL ;
    PORT
      LAYER M4 ;
        RECT  290.725 63.264 291.564 63.288 ;
        RECT  291.516 63.264 291.6 63.288 ;
    END
  END p[72]
  PIN p[73]
    DIRECTION OUTPUT ;
    USE SIGNAL ;
    PORT
      LAYER M4 ;
        RECT  290.725 64.08 291.564 64.104 ;
        RECT  291.516 64.08 291.6 64.104 ;
    END
  END p[73]
  PIN p[74]
    DIRECTION OUTPUT ;
    USE SIGNAL ;
    PORT
      LAYER M4 ;
        RECT  290.725 64.896 291.564 64.92 ;
        RECT  291.516 64.896 291.6 64.92 ;
    END
  END p[74]
  PIN p[75]
    DIRECTION OUTPUT ;
    USE SIGNAL ;
    PORT
      LAYER M4 ;
        RECT  290.725 65.712 291.564 65.736 ;
        RECT  291.516 65.712 291.6 65.736 ;
    END
  END p[75]
  PIN p[76]
    DIRECTION OUTPUT ;
    USE SIGNAL ;
    PORT
      LAYER M4 ;
        RECT  290.725 66.528 291.564 66.552 ;
        RECT  291.516 66.528 291.6 66.552 ;
    END
  END p[76]
  PIN p[77]
    DIRECTION OUTPUT ;
    USE SIGNAL ;
    PORT
      LAYER M4 ;
        RECT  290.725 67.296 291.564 67.32 ;
        RECT  291.516 67.296 291.6 67.32 ;
    END
  END p[77]
  PIN p[78]
    DIRECTION OUTPUT ;
    USE SIGNAL ;
    PORT
      LAYER M4 ;
        RECT  290.725 68.112 291.564 68.136 ;
        RECT  291.516 68.112 291.6 68.136 ;
    END
  END p[78]
  PIN p[79]
    DIRECTION OUTPUT ;
    USE SIGNAL ;
    PORT
      LAYER M4 ;
        RECT  290.725 68.928 291.564 68.952 ;
        RECT  291.516 68.928 291.6 68.952 ;
    END
  END p[79]
  PIN p[7]
    DIRECTION OUTPUT ;
    USE SIGNAL ;
    PORT
      LAYER M4 ;
        RECT  290.725 10.608 291.564 10.632 ;
        RECT  291.516 10.608 291.6 10.632 ;
    END
  END p[7]
  PIN p[80]
    DIRECTION OUTPUT ;
    USE SIGNAL ;
    PORT
      LAYER M4 ;
        RECT  290.725 69.744 291.564 69.768 ;
        RECT  291.516 69.744 291.6 69.768 ;
    END
  END p[80]
  PIN p[81]
    DIRECTION OUTPUT ;
    USE SIGNAL ;
    PORT
      LAYER M4 ;
        RECT  290.725 70.56 291.564 70.584 ;
        RECT  291.516 70.56 291.6 70.584 ;
    END
  END p[81]
  PIN p[82]
    DIRECTION OUTPUT ;
    USE SIGNAL ;
    PORT
      LAYER M4 ;
        RECT  290.725 71.328 291.564 71.352 ;
        RECT  291.516 71.328 291.6 71.352 ;
    END
  END p[82]
  PIN p[83]
    DIRECTION OUTPUT ;
    USE SIGNAL ;
    PORT
      LAYER M4 ;
        RECT  290.725 72.144 291.564 72.168 ;
        RECT  291.516 72.144 291.6 72.168 ;
    END
  END p[83]
  PIN p[84]
    DIRECTION OUTPUT ;
    USE SIGNAL ;
    PORT
      LAYER M4 ;
        RECT  290.725 72.96 291.564 72.984 ;
        RECT  291.516 72.96 291.6 72.984 ;
    END
  END p[84]
  PIN p[85]
    DIRECTION OUTPUT ;
    USE SIGNAL ;
    PORT
      LAYER M4 ;
        RECT  290.725 73.776 291.564 73.8 ;
        RECT  291.516 73.776 291.6 73.8 ;
    END
  END p[85]
  PIN p[86]
    DIRECTION OUTPUT ;
    USE SIGNAL ;
    PORT
      LAYER M4 ;
        RECT  290.725 74.592 291.564 74.616 ;
        RECT  291.516 74.592 291.6 74.616 ;
    END
  END p[86]
  PIN p[87]
    DIRECTION OUTPUT ;
    USE SIGNAL ;
    PORT
      LAYER M4 ;
        RECT  290.725 75.408 291.564 75.432 ;
        RECT  291.516 75.408 291.6 75.432 ;
    END
  END p[87]
  PIN p[88]
    DIRECTION OUTPUT ;
    USE SIGNAL ;
    PORT
      LAYER M4 ;
        RECT  290.725 76.224 291.564 76.248 ;
        RECT  291.516 76.224 291.6 76.248 ;
    END
  END p[88]
  PIN p[89]
    DIRECTION OUTPUT ;
    USE SIGNAL ;
    PORT
      LAYER M4 ;
        RECT  290.725 77.04 291.564 77.064 ;
        RECT  291.516 77.04 291.6 77.064 ;
    END
  END p[89]
  PIN p[8]
    DIRECTION OUTPUT ;
    USE SIGNAL ;
    PORT
      LAYER M4 ;
        RECT  290.725 11.424 291.564 11.448 ;
        RECT  291.516 11.424 291.6 11.448 ;
    END
  END p[8]
  PIN p[90]
    DIRECTION OUTPUT ;
    USE SIGNAL ;
    PORT
      LAYER M4 ;
        RECT  290.725 77.808 291.564 77.832 ;
        RECT  291.516 77.808 291.6 77.832 ;
    END
  END p[90]
  PIN p[91]
    DIRECTION OUTPUT ;
    USE SIGNAL ;
    PORT
      LAYER M4 ;
        RECT  290.725 78.624 291.564 78.648 ;
        RECT  291.516 78.624 291.6 78.648 ;
    END
  END p[91]
  PIN p[92]
    DIRECTION OUTPUT ;
    USE SIGNAL ;
    PORT
      LAYER M4 ;
        RECT  290.725 79.44 291.564 79.464 ;
        RECT  291.516 79.44 291.6 79.464 ;
    END
  END p[92]
  PIN p[93]
    DIRECTION OUTPUT ;
    USE SIGNAL ;
    PORT
      LAYER M4 ;
        RECT  290.725 80.256 291.564 80.28 ;
        RECT  291.516 80.256 291.6 80.28 ;
    END
  END p[93]
  PIN p[94]
    DIRECTION OUTPUT ;
    USE SIGNAL ;
    PORT
      LAYER M4 ;
        RECT  290.725 81.072 291.564 81.096 ;
        RECT  291.516 81.072 291.6 81.096 ;
    END
  END p[94]
  PIN p[95]
    DIRECTION OUTPUT ;
    USE SIGNAL ;
    PORT
      LAYER M4 ;
        RECT  290.725 81.888 291.564 81.912 ;
        RECT  291.516 81.888 291.6 81.912 ;
    END
  END p[95]
  PIN p[96]
    DIRECTION OUTPUT ;
    USE SIGNAL ;
    PORT
      LAYER M4 ;
        RECT  290.725 82.704 291.564 82.728 ;
        RECT  291.516 82.704 291.6 82.728 ;
    END
  END p[96]
  PIN p[97]
    DIRECTION OUTPUT ;
    USE SIGNAL ;
    PORT
      LAYER M4 ;
        RECT  290.725 83.52 291.564 83.544 ;
        RECT  291.516 83.52 291.6 83.544 ;
    END
  END p[97]
  PIN p[98]
    DIRECTION OUTPUT ;
    USE SIGNAL ;
    PORT
      LAYER M4 ;
        RECT  290.725 84.336 291.564 84.36 ;
        RECT  291.516 84.336 291.6 84.36 ;
    END
  END p[98]
  PIN p[99]
    DIRECTION OUTPUT ;
    USE SIGNAL ;
    PORT
      LAYER M4 ;
        RECT  290.725 85.152 291.564 85.176 ;
        RECT  291.516 85.152 291.6 85.176 ;
    END
  END p[99]
  PIN p[9]
    DIRECTION OUTPUT ;
    USE SIGNAL ;
    PORT
      LAYER M4 ;
        RECT  290.725 12.192 291.564 12.216 ;
        RECT  291.516 12.192 291.6 12.216 ;
    END
  END p[9]
  PIN ra[0]
    DIRECTION INPUT ;
    USE SIGNAL ;
    PORT
      LAYER M4 ;
        RECT  290.725 212.352 291.564 212.376 ;
        RECT  291.516 212.352 291.6 212.376 ;
    END
  END ra[0]
  PIN ra[10]
    DIRECTION INPUT ;
    USE SIGNAL ;
    PORT
      LAYER M4 ;
        RECT  290.725 220.464 291.564 220.488 ;
        RECT  291.516 220.464 291.6 220.488 ;
    END
  END ra[10]
  PIN ra[11]
    DIRECTION INPUT ;
    USE SIGNAL ;
    PORT
      LAYER M4 ;
        RECT  290.725 221.28 291.564 221.304 ;
        RECT  291.516 221.28 291.6 221.304 ;
    END
  END ra[11]
  PIN ra[12]
    DIRECTION INPUT ;
    USE SIGNAL ;
    PORT
      LAYER M4 ;
        RECT  290.725 222.096 291.564 222.12 ;
        RECT  291.516 222.096 291.6 222.12 ;
    END
  END ra[12]
  PIN ra[1]
    DIRECTION INPUT ;
    USE SIGNAL ;
    PORT
      LAYER M4 ;
        RECT  290.725 213.168 291.564 213.192 ;
        RECT  291.516 213.168 291.6 213.192 ;
    END
  END ra[1]
  PIN ra[2]
    DIRECTION INPUT ;
    USE SIGNAL ;
    PORT
      LAYER M4 ;
        RECT  290.725 213.984 291.564 214.008 ;
        RECT  291.516 213.984 291.6 214.008 ;
    END
  END ra[2]
  PIN ra[3]
    DIRECTION INPUT ;
    USE SIGNAL ;
    PORT
      LAYER M4 ;
        RECT  290.725 214.8 291.564 214.824 ;
        RECT  291.516 214.8 291.6 214.824 ;
    END
  END ra[3]
  PIN ra[4]
    DIRECTION INPUT ;
    USE SIGNAL ;
    PORT
      LAYER M4 ;
        RECT  290.725 215.616 291.564 215.64 ;
        RECT  291.516 215.616 291.6 215.64 ;
    END
  END ra[4]
  PIN ra[5]
    DIRECTION INPUT ;
    USE SIGNAL ;
    PORT
      LAYER M4 ;
        RECT  290.725 216.384 291.564 216.408 ;
        RECT  291.516 216.384 291.6 216.408 ;
    END
  END ra[5]
  PIN ra[6]
    DIRECTION INPUT ;
    USE SIGNAL ;
    PORT
      LAYER M4 ;
        RECT  290.725 217.2 291.564 217.224 ;
        RECT  291.516 217.2 291.6 217.224 ;
    END
  END ra[6]
  PIN ra[7]
    DIRECTION INPUT ;
    USE SIGNAL ;
    PORT
      LAYER M4 ;
        RECT  290.725 218.016 291.564 218.04 ;
        RECT  291.516 218.016 291.6 218.04 ;
    END
  END ra[7]
  PIN ra[8]
    DIRECTION INPUT ;
    USE SIGNAL ;
    PORT
      LAYER M4 ;
        RECT  290.725 218.832 291.564 218.856 ;
        RECT  291.516 218.832 291.6 218.856 ;
    END
  END ra[8]
  PIN ra[9]
    DIRECTION INPUT ;
    USE SIGNAL ;
    PORT
      LAYER M4 ;
        RECT  290.725 219.648 291.564 219.672 ;
        RECT  291.516 219.648 291.6 219.672 ;
    END
  END ra[9]
  PIN re
    DIRECTION INPUT ;
    USE SIGNAL ;
    PORT
      LAYER M4 ;
        RECT  290.725 222.912 291.564 222.936 ;
        RECT  291.516 222.912 291.6 222.936 ;
    END
  END re
  PIN wa[0]
    DIRECTION INPUT ;
    USE SIGNAL ;
    PORT
      LAYER M4 ;
        RECT  290.725 223.68 291.564 223.704 ;
        RECT  291.516 223.68 291.6 223.704 ;
    END
  END wa[0]
  PIN wa[10]
    DIRECTION INPUT ;
    USE SIGNAL ;
    PORT
      LAYER M4 ;
        RECT  290.725 231.792 291.564 231.816 ;
        RECT  291.516 231.792 291.6 231.816 ;
    END
  END wa[10]
  PIN wa[11]
    DIRECTION INPUT ;
    USE SIGNAL ;
    PORT
      LAYER M4 ;
        RECT  290.725 232.608 291.564 232.632 ;
        RECT  291.516 232.608 291.6 232.632 ;
    END
  END wa[11]
  PIN wa[12]
    DIRECTION INPUT ;
    USE SIGNAL ;
    PORT
      LAYER M4 ;
        RECT  290.725 233.424 291.564 233.448 ;
        RECT  291.516 233.424 291.6 233.448 ;
    END
  END wa[12]
  PIN wa[1]
    DIRECTION INPUT ;
    USE SIGNAL ;
    PORT
      LAYER M4 ;
        RECT  290.725 224.496 291.564 224.52 ;
        RECT  291.516 224.496 291.6 224.52 ;
    END
  END wa[1]
  PIN wa[2]
    DIRECTION INPUT ;
    USE SIGNAL ;
    PORT
      LAYER M4 ;
        RECT  290.725 225.312 291.564 225.336 ;
        RECT  291.516 225.312 291.6 225.336 ;
    END
  END wa[2]
  PIN wa[3]
    DIRECTION INPUT ;
    USE SIGNAL ;
    PORT
      LAYER M4 ;
        RECT  290.725 226.128 291.564 226.152 ;
        RECT  291.516 226.128 291.6 226.152 ;
    END
  END wa[3]
  PIN wa[4]
    DIRECTION INPUT ;
    USE SIGNAL ;
    PORT
      LAYER M4 ;
        RECT  290.725 226.896 291.564 226.92 ;
        RECT  291.516 226.896 291.6 226.92 ;
    END
  END wa[4]
  PIN wa[5]
    DIRECTION INPUT ;
    USE SIGNAL ;
    PORT
      LAYER M4 ;
        RECT  290.725 227.712 291.564 227.736 ;
        RECT  291.516 227.712 291.6 227.736 ;
    END
  END wa[5]
  PIN wa[6]
    DIRECTION INPUT ;
    USE SIGNAL ;
    PORT
      LAYER M4 ;
        RECT  290.725 228.528 291.564 228.552 ;
        RECT  291.516 228.528 291.6 228.552 ;
    END
  END wa[6]
  PIN wa[7]
    DIRECTION INPUT ;
    USE SIGNAL ;
    PORT
      LAYER M4 ;
        RECT  290.725 229.344 291.564 229.368 ;
        RECT  291.516 229.344 291.6 229.368 ;
    END
  END wa[7]
  PIN wa[8]
    DIRECTION INPUT ;
    USE SIGNAL ;
    PORT
      LAYER M4 ;
        RECT  290.725 230.16 291.564 230.184 ;
        RECT  291.516 230.16 291.6 230.184 ;
    END
  END wa[8]
  PIN wa[9]
    DIRECTION INPUT ;
    USE SIGNAL ;
    PORT
      LAYER M4 ;
        RECT  290.725 230.976 291.564 231 ;
        RECT  291.516 230.976 291.6 231 ;
    END
  END wa[9]
  PIN wd[0]
    DIRECTION INPUT ;
    USE SIGNAL ;
    PORT
      LAYER M4 ;
        RECT  290.725 234.24 291.564 234.264 ;
        RECT  291.516 234.24 291.6 234.264 ;
    END
  END wd[0]
  PIN wd[100]
    DIRECTION INPUT ;
    USE SIGNAL ;
    PORT
      LAYER M4 ;
        RECT  290.725 315.264 291.564 315.288 ;
        RECT  291.516 315.264 291.6 315.288 ;
    END
  END wd[100]
  PIN wd[101]
    DIRECTION INPUT ;
    USE SIGNAL ;
    PORT
      LAYER M4 ;
        RECT  290.725 316.08 291.564 316.104 ;
        RECT  291.516 316.08 291.6 316.104 ;
    END
  END wd[101]
  PIN wd[102]
    DIRECTION INPUT ;
    USE SIGNAL ;
    PORT
      LAYER M4 ;
        RECT  290.725 316.896 291.564 316.92 ;
        RECT  291.516 316.896 291.6 316.92 ;
    END
  END wd[102]
  PIN wd[103]
    DIRECTION INPUT ;
    USE SIGNAL ;
    PORT
      LAYER M4 ;
        RECT  290.725 317.712 291.564 317.736 ;
        RECT  291.516 317.712 291.6 317.736 ;
    END
  END wd[103]
  PIN wd[104]
    DIRECTION INPUT ;
    USE SIGNAL ;
    PORT
      LAYER M4 ;
        RECT  290.725 318.48 291.564 318.504 ;
        RECT  291.516 318.48 291.6 318.504 ;
    END
  END wd[104]
  PIN wd[105]
    DIRECTION INPUT ;
    USE SIGNAL ;
    PORT
      LAYER M4 ;
        RECT  290.725 319.296 291.564 319.32 ;
        RECT  291.516 319.296 291.6 319.32 ;
    END
  END wd[105]
  PIN wd[106]
    DIRECTION INPUT ;
    USE SIGNAL ;
    PORT
      LAYER M4 ;
        RECT  290.725 320.112 291.564 320.136 ;
        RECT  291.516 320.112 291.6 320.136 ;
    END
  END wd[106]
  PIN wd[107]
    DIRECTION INPUT ;
    USE SIGNAL ;
    PORT
      LAYER M4 ;
        RECT  290.725 320.928 291.564 320.952 ;
        RECT  291.516 320.928 291.6 320.952 ;
    END
  END wd[107]
  PIN wd[108]
    DIRECTION INPUT ;
    USE SIGNAL ;
    PORT
      LAYER M4 ;
        RECT  290.725 321.744 291.564 321.768 ;
        RECT  291.516 321.744 291.6 321.768 ;
    END
  END wd[108]
  PIN wd[109]
    DIRECTION INPUT ;
    USE SIGNAL ;
    PORT
      LAYER M4 ;
        RECT  290.725 322.56 291.564 322.584 ;
        RECT  291.516 322.56 291.6 322.584 ;
    END
  END wd[109]
  PIN wd[10]
    DIRECTION INPUT ;
    USE SIGNAL ;
    PORT
      LAYER M4 ;
        RECT  290.725 242.352 291.564 242.376 ;
        RECT  291.516 242.352 291.6 242.376 ;
    END
  END wd[10]
  PIN wd[110]
    DIRECTION INPUT ;
    USE SIGNAL ;
    PORT
      LAYER M4 ;
        RECT  290.725 323.376 291.564 323.4 ;
        RECT  291.516 323.376 291.6 323.4 ;
    END
  END wd[110]
  PIN wd[111]
    DIRECTION INPUT ;
    USE SIGNAL ;
    PORT
      LAYER M4 ;
        RECT  290.725 324.192 291.564 324.216 ;
        RECT  291.516 324.192 291.6 324.216 ;
    END
  END wd[111]
  PIN wd[112]
    DIRECTION INPUT ;
    USE SIGNAL ;
    PORT
      LAYER M4 ;
        RECT  290.725 325.008 291.564 325.032 ;
        RECT  291.516 325.008 291.6 325.032 ;
    END
  END wd[112]
  PIN wd[113]
    DIRECTION INPUT ;
    USE SIGNAL ;
    PORT
      LAYER M4 ;
        RECT  290.725 325.776 291.564 325.8 ;
        RECT  291.516 325.776 291.6 325.8 ;
    END
  END wd[113]
  PIN wd[114]
    DIRECTION INPUT ;
    USE SIGNAL ;
    PORT
      LAYER M4 ;
        RECT  290.725 326.592 291.564 326.616 ;
        RECT  291.516 326.592 291.6 326.616 ;
    END
  END wd[114]
  PIN wd[115]
    DIRECTION INPUT ;
    USE SIGNAL ;
    PORT
      LAYER M4 ;
        RECT  290.725 327.408 291.564 327.432 ;
        RECT  291.516 327.408 291.6 327.432 ;
    END
  END wd[115]
  PIN wd[116]
    DIRECTION INPUT ;
    USE SIGNAL ;
    PORT
      LAYER M4 ;
        RECT  290.725 328.224 291.564 328.248 ;
        RECT  291.516 328.224 291.6 328.248 ;
    END
  END wd[116]
  PIN wd[117]
    DIRECTION INPUT ;
    USE SIGNAL ;
    PORT
      LAYER M4 ;
        RECT  290.725 328.992 291.564 329.016 ;
        RECT  291.516 328.992 291.6 329.016 ;
    END
  END wd[117]
  PIN wd[118]
    DIRECTION INPUT ;
    USE SIGNAL ;
    PORT
      LAYER M4 ;
        RECT  290.725 329.808 291.564 329.832 ;
        RECT  291.516 329.808 291.6 329.832 ;
    END
  END wd[118]
  PIN wd[119]
    DIRECTION INPUT ;
    USE SIGNAL ;
    PORT
      LAYER M4 ;
        RECT  290.725 330.624 291.564 330.648 ;
        RECT  291.516 330.624 291.6 330.648 ;
    END
  END wd[119]
  PIN wd[11]
    DIRECTION INPUT ;
    USE SIGNAL ;
    PORT
      LAYER M4 ;
        RECT  290.725 243.168 291.564 243.192 ;
        RECT  291.516 243.168 291.6 243.192 ;
    END
  END wd[11]
  PIN wd[120]
    DIRECTION INPUT ;
    USE SIGNAL ;
    PORT
      LAYER M4 ;
        RECT  290.725 331.44 291.564 331.464 ;
        RECT  291.516 331.44 291.6 331.464 ;
    END
  END wd[120]
  PIN wd[121]
    DIRECTION INPUT ;
    USE SIGNAL ;
    PORT
      LAYER M4 ;
        RECT  290.725 332.256 291.564 332.28 ;
        RECT  291.516 332.256 291.6 332.28 ;
    END
  END wd[121]
  PIN wd[122]
    DIRECTION INPUT ;
    USE SIGNAL ;
    PORT
      LAYER M4 ;
        RECT  290.725 333.072 291.564 333.096 ;
        RECT  291.516 333.072 291.6 333.096 ;
    END
  END wd[122]
  PIN wd[123]
    DIRECTION INPUT ;
    USE SIGNAL ;
    PORT
      LAYER M4 ;
        RECT  290.725 333.888 291.564 333.912 ;
        RECT  291.516 333.888 291.6 333.912 ;
    END
  END wd[123]
  PIN wd[124]
    DIRECTION INPUT ;
    USE SIGNAL ;
    PORT
      LAYER M4 ;
        RECT  290.725 334.704 291.564 334.728 ;
        RECT  291.516 334.704 291.6 334.728 ;
    END
  END wd[124]
  PIN wd[125]
    DIRECTION INPUT ;
    USE SIGNAL ;
    PORT
      LAYER M4 ;
        RECT  290.725 335.52 291.564 335.544 ;
        RECT  291.516 335.52 291.6 335.544 ;
    END
  END wd[125]
  PIN wd[126]
    DIRECTION INPUT ;
    USE SIGNAL ;
    PORT
      LAYER M4 ;
        RECT  290.725 336.336 291.564 336.36 ;
        RECT  291.516 336.336 291.6 336.36 ;
    END
  END wd[126]
  PIN wd[127]
    DIRECTION INPUT ;
    USE SIGNAL ;
    PORT
      LAYER M4 ;
        RECT  290.725 337.152 291.564 337.176 ;
        RECT  291.516 337.152 291.6 337.176 ;
    END
  END wd[127]
  PIN wd[128]
    DIRECTION INPUT ;
    USE SIGNAL ;
    PORT
      LAYER M4 ;
        RECT  290.725 337.92 291.564 337.944 ;
        RECT  291.516 337.92 291.6 337.944 ;
    END
  END wd[128]
  PIN wd[129]
    DIRECTION INPUT ;
    USE SIGNAL ;
    PORT
      LAYER M4 ;
        RECT  290.725 338.736 291.564 338.76 ;
        RECT  291.516 338.736 291.6 338.76 ;
    END
  END wd[129]
  PIN wd[12]
    DIRECTION INPUT ;
    USE SIGNAL ;
    PORT
      LAYER M4 ;
        RECT  290.725 243.936 291.564 243.96 ;
        RECT  291.516 243.936 291.6 243.96 ;
    END
  END wd[12]
  PIN wd[130]
    DIRECTION INPUT ;
    USE SIGNAL ;
    PORT
      LAYER M4 ;
        RECT  290.725 339.552 291.564 339.576 ;
        RECT  291.516 339.552 291.6 339.576 ;
    END
  END wd[130]
  PIN wd[131]
    DIRECTION INPUT ;
    USE SIGNAL ;
    PORT
      LAYER M4 ;
        RECT  290.725 340.368 291.564 340.392 ;
        RECT  291.516 340.368 291.6 340.392 ;
    END
  END wd[131]
  PIN wd[132]
    DIRECTION INPUT ;
    USE SIGNAL ;
    PORT
      LAYER M4 ;
        RECT  290.725 341.184 291.564 341.208 ;
        RECT  291.516 341.184 291.6 341.208 ;
    END
  END wd[132]
  PIN wd[133]
    DIRECTION INPUT ;
    USE SIGNAL ;
    PORT
      LAYER M4 ;
        RECT  290.725 342 291.564 342.024 ;
        RECT  291.516 342 291.6 342.024 ;
    END
  END wd[133]
  PIN wd[134]
    DIRECTION INPUT ;
    USE SIGNAL ;
    PORT
      LAYER M4 ;
        RECT  290.725 342.816 291.564 342.84 ;
        RECT  291.516 342.816 291.6 342.84 ;
    END
  END wd[134]
  PIN wd[135]
    DIRECTION INPUT ;
    USE SIGNAL ;
    PORT
      LAYER M4 ;
        RECT  290.725 343.632 291.564 343.656 ;
        RECT  291.516 343.632 291.6 343.656 ;
    END
  END wd[135]
  PIN wd[136]
    DIRECTION INPUT ;
    USE SIGNAL ;
    PORT
      LAYER M4 ;
        RECT  290.725 344.448 291.564 344.472 ;
        RECT  291.516 344.448 291.6 344.472 ;
    END
  END wd[136]
  PIN wd[137]
    DIRECTION INPUT ;
    USE SIGNAL ;
    PORT
      LAYER M4 ;
        RECT  290.725 345.264 291.564 345.288 ;
        RECT  291.516 345.264 291.6 345.288 ;
    END
  END wd[137]
  PIN wd[138]
    DIRECTION INPUT ;
    USE SIGNAL ;
    PORT
      LAYER M4 ;
        RECT  290.725 346.08 291.564 346.104 ;
        RECT  291.516 346.08 291.6 346.104 ;
    END
  END wd[138]
  PIN wd[139]
    DIRECTION INPUT ;
    USE SIGNAL ;
    PORT
      LAYER M4 ;
        RECT  290.725 346.848 291.564 346.872 ;
        RECT  291.516 346.848 291.6 346.872 ;
    END
  END wd[139]
  PIN wd[13]
    DIRECTION INPUT ;
    USE SIGNAL ;
    PORT
      LAYER M4 ;
        RECT  290.725 244.752 291.564 244.776 ;
        RECT  291.516 244.752 291.6 244.776 ;
    END
  END wd[13]
  PIN wd[140]
    DIRECTION INPUT ;
    USE SIGNAL ;
    PORT
      LAYER M4 ;
        RECT  290.725 347.664 291.564 347.688 ;
        RECT  291.516 347.664 291.6 347.688 ;
    END
  END wd[140]
  PIN wd[141]
    DIRECTION INPUT ;
    USE SIGNAL ;
    PORT
      LAYER M4 ;
        RECT  290.725 348.48 291.564 348.504 ;
        RECT  291.516 348.48 291.6 348.504 ;
    END
  END wd[141]
  PIN wd[142]
    DIRECTION INPUT ;
    USE SIGNAL ;
    PORT
      LAYER M4 ;
        RECT  290.725 349.296 291.564 349.32 ;
        RECT  291.516 349.296 291.6 349.32 ;
    END
  END wd[142]
  PIN wd[143]
    DIRECTION INPUT ;
    USE SIGNAL ;
    PORT
      LAYER M4 ;
        RECT  290.725 350.112 291.564 350.136 ;
        RECT  291.516 350.112 291.6 350.136 ;
    END
  END wd[143]
  PIN wd[144]
    DIRECTION INPUT ;
    USE SIGNAL ;
    PORT
      LAYER M4 ;
        RECT  290.725 350.928 291.564 350.952 ;
        RECT  291.516 350.928 291.6 350.952 ;
    END
  END wd[144]
  PIN wd[145]
    DIRECTION INPUT ;
    USE SIGNAL ;
    PORT
      LAYER M4 ;
        RECT  290.725 351.696 291.564 351.72 ;
        RECT  291.516 351.696 291.6 351.72 ;
    END
  END wd[145]
  PIN wd[146]
    DIRECTION INPUT ;
    USE SIGNAL ;
    PORT
      LAYER M4 ;
        RECT  290.725 352.512 291.564 352.536 ;
        RECT  291.516 352.512 291.6 352.536 ;
    END
  END wd[146]
  PIN wd[147]
    DIRECTION INPUT ;
    USE SIGNAL ;
    PORT
      LAYER M4 ;
        RECT  290.725 353.328 291.564 353.352 ;
        RECT  291.516 353.328 291.6 353.352 ;
    END
  END wd[147]
  PIN wd[148]
    DIRECTION INPUT ;
    USE SIGNAL ;
    PORT
      LAYER M4 ;
        RECT  290.725 354.144 291.564 354.168 ;
        RECT  291.516 354.144 291.6 354.168 ;
    END
  END wd[148]
  PIN wd[149]
    DIRECTION INPUT ;
    USE SIGNAL ;
    PORT
      LAYER M4 ;
        RECT  290.725 354.96 291.564 354.984 ;
        RECT  291.516 354.96 291.6 354.984 ;
    END
  END wd[149]
  PIN wd[14]
    DIRECTION INPUT ;
    USE SIGNAL ;
    PORT
      LAYER M4 ;
        RECT  290.725 245.568 291.564 245.592 ;
        RECT  291.516 245.568 291.6 245.592 ;
    END
  END wd[14]
  PIN wd[150]
    DIRECTION INPUT ;
    USE SIGNAL ;
    PORT
      LAYER M4 ;
        RECT  290.725 355.776 291.564 355.8 ;
        RECT  291.516 355.776 291.6 355.8 ;
    END
  END wd[150]
  PIN wd[151]
    DIRECTION INPUT ;
    USE SIGNAL ;
    PORT
      LAYER M4 ;
        RECT  290.725 356.592 291.564 356.616 ;
        RECT  291.516 356.592 291.6 356.616 ;
    END
  END wd[151]
  PIN wd[152]
    DIRECTION INPUT ;
    USE SIGNAL ;
    PORT
      LAYER M4 ;
        RECT  290.725 357.36 291.564 357.384 ;
        RECT  291.516 357.36 291.6 357.384 ;
    END
  END wd[152]
  PIN wd[153]
    DIRECTION INPUT ;
    USE SIGNAL ;
    PORT
      LAYER M4 ;
        RECT  290.725 358.176 291.564 358.2 ;
        RECT  291.516 358.176 291.6 358.2 ;
    END
  END wd[153]
  PIN wd[154]
    DIRECTION INPUT ;
    USE SIGNAL ;
    PORT
      LAYER M4 ;
        RECT  290.725 358.992 291.564 359.016 ;
        RECT  291.516 358.992 291.6 359.016 ;
    END
  END wd[154]
  PIN wd[155]
    DIRECTION INPUT ;
    USE SIGNAL ;
    PORT
      LAYER M4 ;
        RECT  290.725 359.808 291.564 359.832 ;
        RECT  291.516 359.808 291.6 359.832 ;
    END
  END wd[155]
  PIN wd[156]
    DIRECTION INPUT ;
    USE SIGNAL ;
    PORT
      LAYER M4 ;
        RECT  290.725 360.624 291.564 360.648 ;
        RECT  291.516 360.624 291.6 360.648 ;
    END
  END wd[156]
  PIN wd[157]
    DIRECTION INPUT ;
    USE SIGNAL ;
    PORT
      LAYER M4 ;
        RECT  290.725 361.44 291.564 361.464 ;
        RECT  291.516 361.44 291.6 361.464 ;
    END
  END wd[157]
  PIN wd[158]
    DIRECTION INPUT ;
    USE SIGNAL ;
    PORT
      LAYER M4 ;
        RECT  290.725 362.256 291.564 362.28 ;
        RECT  291.516 362.256 291.6 362.28 ;
    END
  END wd[158]
  PIN wd[159]
    DIRECTION INPUT ;
    USE SIGNAL ;
    PORT
      LAYER M4 ;
        RECT  290.725 363.072 291.564 363.096 ;
        RECT  291.516 363.072 291.6 363.096 ;
    END
  END wd[159]
  PIN wd[15]
    DIRECTION INPUT ;
    USE SIGNAL ;
    PORT
      LAYER M4 ;
        RECT  290.725 246.384 291.564 246.408 ;
        RECT  291.516 246.384 291.6 246.408 ;
    END
  END wd[15]
  PIN wd[160]
    DIRECTION INPUT ;
    USE SIGNAL ;
    PORT
      LAYER M4 ;
        RECT  290.725 363.888 291.564 363.912 ;
        RECT  291.516 363.888 291.6 363.912 ;
    END
  END wd[160]
  PIN wd[161]
    DIRECTION INPUT ;
    USE SIGNAL ;
    PORT
      LAYER M4 ;
        RECT  290.725 364.704 291.564 364.728 ;
        RECT  291.516 364.704 291.6 364.728 ;
    END
  END wd[161]
  PIN wd[162]
    DIRECTION INPUT ;
    USE SIGNAL ;
    PORT
      LAYER M4 ;
        RECT  290.725 365.472 291.564 365.496 ;
        RECT  291.516 365.472 291.6 365.496 ;
    END
  END wd[162]
  PIN wd[163]
    DIRECTION INPUT ;
    USE SIGNAL ;
    PORT
      LAYER M4 ;
        RECT  290.725 366.288 291.564 366.312 ;
        RECT  291.516 366.288 291.6 366.312 ;
    END
  END wd[163]
  PIN wd[164]
    DIRECTION INPUT ;
    USE SIGNAL ;
    PORT
      LAYER M4 ;
        RECT  290.725 367.104 291.564 367.128 ;
        RECT  291.516 367.104 291.6 367.128 ;
    END
  END wd[164]
  PIN wd[165]
    DIRECTION INPUT ;
    USE SIGNAL ;
    PORT
      LAYER M4 ;
        RECT  290.725 367.92 291.564 367.944 ;
        RECT  291.516 367.92 291.6 367.944 ;
    END
  END wd[165]
  PIN wd[166]
    DIRECTION INPUT ;
    USE SIGNAL ;
    PORT
      LAYER M4 ;
        RECT  290.725 368.736 291.564 368.76 ;
        RECT  291.516 368.736 291.6 368.76 ;
    END
  END wd[166]
  PIN wd[167]
    DIRECTION INPUT ;
    USE SIGNAL ;
    PORT
      LAYER M4 ;
        RECT  290.725 369.552 291.564 369.576 ;
        RECT  291.516 369.552 291.6 369.576 ;
    END
  END wd[167]
  PIN wd[168]
    DIRECTION INPUT ;
    USE SIGNAL ;
    PORT
      LAYER M4 ;
        RECT  290.725 370.368 291.564 370.392 ;
        RECT  291.516 370.368 291.6 370.392 ;
    END
  END wd[168]
  PIN wd[169]
    DIRECTION INPUT ;
    USE SIGNAL ;
    PORT
      LAYER M4 ;
        RECT  290.725 371.184 291.564 371.208 ;
        RECT  291.516 371.184 291.6 371.208 ;
    END
  END wd[169]
  PIN wd[16]
    DIRECTION INPUT ;
    USE SIGNAL ;
    PORT
      LAYER M4 ;
        RECT  290.725 247.2 291.564 247.224 ;
        RECT  291.516 247.2 291.6 247.224 ;
    END
  END wd[16]
  PIN wd[170]
    DIRECTION INPUT ;
    USE SIGNAL ;
    PORT
      LAYER M4 ;
        RECT  290.725 372 291.564 372.024 ;
        RECT  291.516 372 291.6 372.024 ;
    END
  END wd[170]
  PIN wd[171]
    DIRECTION INPUT ;
    USE SIGNAL ;
    PORT
      LAYER M4 ;
        RECT  290.725 372.816 291.564 372.84 ;
        RECT  291.516 372.816 291.6 372.84 ;
    END
  END wd[171]
  PIN wd[172]
    DIRECTION INPUT ;
    USE SIGNAL ;
    PORT
      LAYER M4 ;
        RECT  290.725 373.632 291.564 373.656 ;
        RECT  291.516 373.632 291.6 373.656 ;
    END
  END wd[172]
  PIN wd[173]
    DIRECTION INPUT ;
    USE SIGNAL ;
    PORT
      LAYER M4 ;
        RECT  290.725 374.4 291.564 374.424 ;
        RECT  291.516 374.4 291.6 374.424 ;
    END
  END wd[173]
  PIN wd[174]
    DIRECTION INPUT ;
    USE SIGNAL ;
    PORT
      LAYER M4 ;
        RECT  290.725 375.216 291.564 375.24 ;
        RECT  291.516 375.216 291.6 375.24 ;
    END
  END wd[174]
  PIN wd[175]
    DIRECTION INPUT ;
    USE SIGNAL ;
    PORT
      LAYER M4 ;
        RECT  290.725 376.032 291.564 376.056 ;
        RECT  291.516 376.032 291.6 376.056 ;
    END
  END wd[175]
  PIN wd[176]
    DIRECTION INPUT ;
    USE SIGNAL ;
    PORT
      LAYER M4 ;
        RECT  290.725 376.8 291.564 376.824 ;
        RECT  291.516 376.8 291.6 376.824 ;
    END
  END wd[176]
  PIN wd[177]
    DIRECTION INPUT ;
    USE SIGNAL ;
    PORT
      LAYER M4 ;
        RECT  290.725 377.616 291.564 377.64 ;
        RECT  291.516 377.616 291.6 377.64 ;
    END
  END wd[177]
  PIN wd[178]
    DIRECTION INPUT ;
    USE SIGNAL ;
    PORT
      LAYER M4 ;
        RECT  290.725 378.432 291.564 378.456 ;
        RECT  291.516 378.432 291.6 378.456 ;
    END
  END wd[178]
  PIN wd[179]
    DIRECTION INPUT ;
    USE SIGNAL ;
    PORT
      LAYER M4 ;
        RECT  290.725 379.248 291.564 379.272 ;
        RECT  291.516 379.248 291.6 379.272 ;
    END
  END wd[179]
  PIN wd[17]
    DIRECTION INPUT ;
    USE SIGNAL ;
    PORT
      LAYER M4 ;
        RECT  290.725 248.016 291.564 248.04 ;
        RECT  291.516 248.016 291.6 248.04 ;
    END
  END wd[17]
  PIN wd[180]
    DIRECTION INPUT ;
    USE SIGNAL ;
    PORT
      LAYER M4 ;
        RECT  290.725 380.064 291.564 380.088 ;
        RECT  291.516 380.064 291.6 380.088 ;
    END
  END wd[180]
  PIN wd[181]
    DIRECTION INPUT ;
    USE SIGNAL ;
    PORT
      LAYER M4 ;
        RECT  290.725 380.88 291.564 380.904 ;
        RECT  291.516 380.88 291.6 380.904 ;
    END
  END wd[181]
  PIN wd[182]
    DIRECTION INPUT ;
    USE SIGNAL ;
    PORT
      LAYER M4 ;
        RECT  290.725 381.696 291.564 381.72 ;
        RECT  291.516 381.696 291.6 381.72 ;
    END
  END wd[182]
  PIN wd[183]
    DIRECTION INPUT ;
    USE SIGNAL ;
    PORT
      LAYER M4 ;
        RECT  290.725 382.512 291.564 382.536 ;
        RECT  291.516 382.512 291.6 382.536 ;
    END
  END wd[183]
  PIN wd[184]
    DIRECTION INPUT ;
    USE SIGNAL ;
    PORT
      LAYER M4 ;
        RECT  290.725 383.328 291.564 383.352 ;
        RECT  291.516 383.328 291.6 383.352 ;
    END
  END wd[184]
  PIN wd[185]
    DIRECTION INPUT ;
    USE SIGNAL ;
    PORT
      LAYER M4 ;
        RECT  290.725 384.144 291.564 384.168 ;
        RECT  291.516 384.144 291.6 384.168 ;
    END
  END wd[185]
  PIN wd[186]
    DIRECTION INPUT ;
    USE SIGNAL ;
    PORT
      LAYER M4 ;
        RECT  290.725 384.912 291.564 384.936 ;
        RECT  291.516 384.912 291.6 384.936 ;
    END
  END wd[186]
  PIN wd[187]
    DIRECTION INPUT ;
    USE SIGNAL ;
    PORT
      LAYER M4 ;
        RECT  290.725 385.728 291.564 385.752 ;
        RECT  291.516 385.728 291.6 385.752 ;
    END
  END wd[187]
  PIN wd[188]
    DIRECTION INPUT ;
    USE SIGNAL ;
    PORT
      LAYER M4 ;
        RECT  290.725 386.544 291.564 386.568 ;
        RECT  291.516 386.544 291.6 386.568 ;
    END
  END wd[188]
  PIN wd[189]
    DIRECTION INPUT ;
    USE SIGNAL ;
    PORT
      LAYER M4 ;
        RECT  290.725 387.36 291.564 387.384 ;
        RECT  291.516 387.36 291.6 387.384 ;
    END
  END wd[189]
  PIN wd[18]
    DIRECTION INPUT ;
    USE SIGNAL ;
    PORT
      LAYER M4 ;
        RECT  290.725 248.832 291.564 248.856 ;
        RECT  291.516 248.832 291.6 248.856 ;
    END
  END wd[18]
  PIN wd[190]
    DIRECTION INPUT ;
    USE SIGNAL ;
    PORT
      LAYER M4 ;
        RECT  290.725 388.176 291.564 388.2 ;
        RECT  291.516 388.176 291.6 388.2 ;
    END
  END wd[190]
  PIN wd[191]
    DIRECTION INPUT ;
    USE SIGNAL ;
    PORT
      LAYER M4 ;
        RECT  290.725 388.992 291.564 389.016 ;
        RECT  291.516 388.992 291.6 389.016 ;
    END
  END wd[191]
  PIN wd[192]
    DIRECTION INPUT ;
    USE SIGNAL ;
    PORT
      LAYER M4 ;
        RECT  290.725 389.808 291.564 389.832 ;
        RECT  291.516 389.808 291.6 389.832 ;
    END
  END wd[192]
  PIN wd[193]
    DIRECTION INPUT ;
    USE SIGNAL ;
    PORT
      LAYER M4 ;
        RECT  290.725 390.624 291.564 390.648 ;
        RECT  291.516 390.624 291.6 390.648 ;
    END
  END wd[193]
  PIN wd[194]
    DIRECTION INPUT ;
    USE SIGNAL ;
    PORT
      LAYER M4 ;
        RECT  290.725 391.44 291.564 391.464 ;
        RECT  291.516 391.44 291.6 391.464 ;
    END
  END wd[194]
  PIN wd[195]
    DIRECTION INPUT ;
    USE SIGNAL ;
    PORT
      LAYER M4 ;
        RECT  290.725 392.256 291.564 392.28 ;
        RECT  291.516 392.256 291.6 392.28 ;
    END
  END wd[195]
  PIN wd[196]
    DIRECTION INPUT ;
    USE SIGNAL ;
    PORT
      LAYER M4 ;
        RECT  290.725 393.072 291.564 393.096 ;
        RECT  291.516 393.072 291.6 393.096 ;
    END
  END wd[196]
  PIN wd[197]
    DIRECTION INPUT ;
    USE SIGNAL ;
    PORT
      LAYER M4 ;
        RECT  290.725 393.84 291.564 393.864 ;
        RECT  291.516 393.84 291.6 393.864 ;
    END
  END wd[197]
  PIN wd[198]
    DIRECTION INPUT ;
    USE SIGNAL ;
    PORT
      LAYER M4 ;
        RECT  290.725 394.656 291.564 394.68 ;
        RECT  291.516 394.656 291.6 394.68 ;
    END
  END wd[198]
  PIN wd[199]
    DIRECTION INPUT ;
    USE SIGNAL ;
    PORT
      LAYER M4 ;
        RECT  290.725 395.472 291.564 395.496 ;
        RECT  291.516 395.472 291.6 395.496 ;
    END
  END wd[199]
  PIN wd[19]
    DIRECTION INPUT ;
    USE SIGNAL ;
    PORT
      LAYER M4 ;
        RECT  290.725 249.6 291.564 249.624 ;
        RECT  291.516 249.6 291.6 249.624 ;
    END
  END wd[19]
  PIN wd[1]
    DIRECTION INPUT ;
    USE SIGNAL ;
    PORT
      LAYER M4 ;
        RECT  290.725 235.056 291.564 235.08 ;
        RECT  291.516 235.056 291.6 235.08 ;
    END
  END wd[1]
  PIN wd[200]
    DIRECTION INPUT ;
    USE SIGNAL ;
    PORT
      LAYER M4 ;
        RECT  290.725 396.288 291.564 396.312 ;
        RECT  291.516 396.288 291.6 396.312 ;
    END
  END wd[200]
  PIN wd[201]
    DIRECTION INPUT ;
    USE SIGNAL ;
    PORT
      LAYER M4 ;
        RECT  290.725 397.104 291.564 397.128 ;
        RECT  291.516 397.104 291.6 397.128 ;
    END
  END wd[201]
  PIN wd[202]
    DIRECTION INPUT ;
    USE SIGNAL ;
    PORT
      LAYER M4 ;
        RECT  290.725 397.92 291.564 397.944 ;
        RECT  291.516 397.92 291.6 397.944 ;
    END
  END wd[202]
  PIN wd[203]
    DIRECTION INPUT ;
    USE SIGNAL ;
    PORT
      LAYER M4 ;
        RECT  290.725 398.736 291.564 398.76 ;
        RECT  291.516 398.736 291.6 398.76 ;
    END
  END wd[203]
  PIN wd[204]
    DIRECTION INPUT ;
    USE SIGNAL ;
    PORT
      LAYER M4 ;
        RECT  290.725 399.552 291.564 399.576 ;
        RECT  291.516 399.552 291.6 399.576 ;
    END
  END wd[204]
  PIN wd[205]
    DIRECTION INPUT ;
    USE SIGNAL ;
    PORT
      LAYER M4 ;
        RECT  290.725 400.368 291.564 400.392 ;
        RECT  291.516 400.368 291.6 400.392 ;
    END
  END wd[205]
  PIN wd[206]
    DIRECTION INPUT ;
    USE SIGNAL ;
    PORT
      LAYER M4 ;
        RECT  290.725 401.184 291.564 401.208 ;
        RECT  291.516 401.184 291.6 401.208 ;
    END
  END wd[206]
  PIN wd[207]
    DIRECTION INPUT ;
    USE SIGNAL ;
    PORT
      LAYER M4 ;
        RECT  290.725 401.952 291.564 401.976 ;
        RECT  291.516 401.952 291.6 401.976 ;
    END
  END wd[207]
  PIN wd[208]
    DIRECTION INPUT ;
    USE SIGNAL ;
    PORT
      LAYER M4 ;
        RECT  290.725 402.768 291.564 402.792 ;
        RECT  291.516 402.768 291.6 402.792 ;
    END
  END wd[208]
  PIN wd[209]
    DIRECTION INPUT ;
    USE SIGNAL ;
    PORT
      LAYER M4 ;
        RECT  290.725 403.536 291.564 403.56 ;
        RECT  291.516 403.536 291.6 403.56 ;
    END
  END wd[209]
  PIN wd[20]
    DIRECTION INPUT ;
    USE SIGNAL ;
    PORT
      LAYER M4 ;
        RECT  290.725 250.416 291.564 250.44 ;
        RECT  291.516 250.416 291.6 250.44 ;
    END
  END wd[20]
  PIN wd[210]
    DIRECTION INPUT ;
    USE SIGNAL ;
    PORT
      LAYER M4 ;
        RECT  290.725 404.352 291.564 404.376 ;
        RECT  291.516 404.352 291.6 404.376 ;
    END
  END wd[210]
  PIN wd[211]
    DIRECTION INPUT ;
    USE SIGNAL ;
    PORT
      LAYER M4 ;
        RECT  290.725 405.168 291.564 405.192 ;
        RECT  291.516 405.168 291.6 405.192 ;
    END
  END wd[211]
  PIN wd[212]
    DIRECTION INPUT ;
    USE SIGNAL ;
    PORT
      LAYER M4 ;
        RECT  290.725 405.984 291.564 406.008 ;
        RECT  291.516 405.984 291.6 406.008 ;
    END
  END wd[212]
  PIN wd[213]
    DIRECTION INPUT ;
    USE SIGNAL ;
    PORT
      LAYER M4 ;
        RECT  290.725 406.8 291.564 406.824 ;
        RECT  291.516 406.8 291.6 406.824 ;
    END
  END wd[213]
  PIN wd[214]
    DIRECTION INPUT ;
    USE SIGNAL ;
    PORT
      LAYER M4 ;
        RECT  290.725 407.616 291.564 407.64 ;
        RECT  291.516 407.616 291.6 407.64 ;
    END
  END wd[214]
  PIN wd[215]
    DIRECTION INPUT ;
    USE SIGNAL ;
    PORT
      LAYER M4 ;
        RECT  290.725 408.432 291.564 408.456 ;
        RECT  291.516 408.432 291.6 408.456 ;
    END
  END wd[215]
  PIN wd[216]
    DIRECTION INPUT ;
    USE SIGNAL ;
    PORT
      LAYER M4 ;
        RECT  290.725 409.248 291.564 409.272 ;
        RECT  291.516 409.248 291.6 409.272 ;
    END
  END wd[216]
  PIN wd[217]
    DIRECTION INPUT ;
    USE SIGNAL ;
    PORT
      LAYER M4 ;
        RECT  290.725 410.064 291.564 410.088 ;
        RECT  291.516 410.064 291.6 410.088 ;
    END
  END wd[217]
  PIN wd[218]
    DIRECTION INPUT ;
    USE SIGNAL ;
    PORT
      LAYER M4 ;
        RECT  290.725 410.88 291.564 410.904 ;
        RECT  291.516 410.88 291.6 410.904 ;
    END
  END wd[218]
  PIN wd[219]
    DIRECTION INPUT ;
    USE SIGNAL ;
    PORT
      LAYER M4 ;
        RECT  290.725 411.696 291.564 411.72 ;
        RECT  291.516 411.696 291.6 411.72 ;
    END
  END wd[219]
  PIN wd[21]
    DIRECTION INPUT ;
    USE SIGNAL ;
    PORT
      LAYER M4 ;
        RECT  290.725 251.232 291.564 251.256 ;
        RECT  291.516 251.232 291.6 251.256 ;
    END
  END wd[21]
  PIN wd[220]
    DIRECTION INPUT ;
    USE SIGNAL ;
    PORT
      LAYER M4 ;
        RECT  290.725 412.464 291.564 412.488 ;
        RECT  291.516 412.464 291.6 412.488 ;
    END
  END wd[220]
  PIN wd[221]
    DIRECTION INPUT ;
    USE SIGNAL ;
    PORT
      LAYER M4 ;
        RECT  290.725 413.28 291.564 413.304 ;
        RECT  291.516 413.28 291.6 413.304 ;
    END
  END wd[221]
  PIN wd[222]
    DIRECTION INPUT ;
    USE SIGNAL ;
    PORT
      LAYER M4 ;
        RECT  290.725 414.096 291.564 414.12 ;
        RECT  291.516 414.096 291.6 414.12 ;
    END
  END wd[222]
  PIN wd[223]
    DIRECTION INPUT ;
    USE SIGNAL ;
    PORT
      LAYER M4 ;
        RECT  290.725 414.912 291.564 414.936 ;
        RECT  291.516 414.912 291.6 414.936 ;
    END
  END wd[223]
  PIN wd[224]
    DIRECTION INPUT ;
    USE SIGNAL ;
    PORT
      LAYER M4 ;
        RECT  290.725 415.728 291.564 415.752 ;
        RECT  291.516 415.728 291.6 415.752 ;
    END
  END wd[224]
  PIN wd[225]
    DIRECTION INPUT ;
    USE SIGNAL ;
    PORT
      LAYER M4 ;
        RECT  290.725 416.544 291.564 416.568 ;
        RECT  291.516 416.544 291.6 416.568 ;
    END
  END wd[225]
  PIN wd[226]
    DIRECTION INPUT ;
    USE SIGNAL ;
    PORT
      LAYER M4 ;
        RECT  290.725 417.36 291.564 417.384 ;
        RECT  291.516 417.36 291.6 417.384 ;
    END
  END wd[226]
  PIN wd[227]
    DIRECTION INPUT ;
    USE SIGNAL ;
    PORT
      LAYER M4 ;
        RECT  290.725 418.176 291.564 418.2 ;
        RECT  291.516 418.176 291.6 418.2 ;
    END
  END wd[227]
  PIN wd[228]
    DIRECTION INPUT ;
    USE SIGNAL ;
    PORT
      LAYER M4 ;
        RECT  290.725 418.992 291.564 419.016 ;
        RECT  291.516 418.992 291.6 419.016 ;
    END
  END wd[228]
  PIN wd[229]
    DIRECTION INPUT ;
    USE SIGNAL ;
    PORT
      LAYER M4 ;
        RECT  290.725 419.808 291.564 419.832 ;
        RECT  291.516 419.808 291.6 419.832 ;
    END
  END wd[229]
  PIN wd[22]
    DIRECTION INPUT ;
    USE SIGNAL ;
    PORT
      LAYER M4 ;
        RECT  290.725 252.048 291.564 252.072 ;
        RECT  291.516 252.048 291.6 252.072 ;
    END
  END wd[22]
  PIN wd[230]
    DIRECTION INPUT ;
    USE SIGNAL ;
    PORT
      LAYER M4 ;
        RECT  290.725 420.624 291.564 420.648 ;
        RECT  291.516 420.624 291.6 420.648 ;
    END
  END wd[230]
  PIN wd[231]
    DIRECTION INPUT ;
    USE SIGNAL ;
    PORT
      LAYER M4 ;
        RECT  290.725 421.392 291.564 421.416 ;
        RECT  291.516 421.392 291.6 421.416 ;
    END
  END wd[231]
  PIN wd[232]
    DIRECTION INPUT ;
    USE SIGNAL ;
    PORT
      LAYER M4 ;
        RECT  290.725 422.208 291.564 422.232 ;
        RECT  291.516 422.208 291.6 422.232 ;
    END
  END wd[232]
  PIN wd[233]
    DIRECTION INPUT ;
    USE SIGNAL ;
    PORT
      LAYER M4 ;
        RECT  290.725 423.024 291.564 423.048 ;
        RECT  291.516 423.024 291.6 423.048 ;
    END
  END wd[233]
  PIN wd[234]
    DIRECTION INPUT ;
    USE SIGNAL ;
    PORT
      LAYER M4 ;
        RECT  290.725 423.84 291.564 423.864 ;
        RECT  291.516 423.84 291.6 423.864 ;
    END
  END wd[234]
  PIN wd[235]
    DIRECTION INPUT ;
    USE SIGNAL ;
    PORT
      LAYER M4 ;
        RECT  290.725 424.656 291.564 424.68 ;
        RECT  291.516 424.656 291.6 424.68 ;
    END
  END wd[235]
  PIN wd[236]
    DIRECTION INPUT ;
    USE SIGNAL ;
    PORT
      LAYER M4 ;
        RECT  290.725 425.472 291.564 425.496 ;
        RECT  291.516 425.472 291.6 425.496 ;
    END
  END wd[236]
  PIN wd[237]
    DIRECTION INPUT ;
    USE SIGNAL ;
    PORT
      LAYER M4 ;
        RECT  290.725 426.288 291.564 426.312 ;
        RECT  291.516 426.288 291.6 426.312 ;
    END
  END wd[237]
  PIN wd[238]
    DIRECTION INPUT ;
    USE SIGNAL ;
    PORT
      LAYER M4 ;
        RECT  290.725 427.104 291.564 427.128 ;
        RECT  291.516 427.104 291.6 427.128 ;
    END
  END wd[238]
  PIN wd[239]
    DIRECTION INPUT ;
    USE SIGNAL ;
    PORT
      LAYER M4 ;
        RECT  290.725 427.872 291.564 427.896 ;
        RECT  291.516 427.872 291.6 427.896 ;
    END
  END wd[239]
  PIN wd[23]
    DIRECTION INPUT ;
    USE SIGNAL ;
    PORT
      LAYER M4 ;
        RECT  290.725 252.864 291.564 252.888 ;
        RECT  291.516 252.864 291.6 252.888 ;
    END
  END wd[23]
  PIN wd[240]
    DIRECTION INPUT ;
    USE SIGNAL ;
    PORT
      LAYER M4 ;
        RECT  290.725 428.688 291.564 428.712 ;
        RECT  291.516 428.688 291.6 428.712 ;
    END
  END wd[240]
  PIN wd[241]
    DIRECTION INPUT ;
    USE SIGNAL ;
    PORT
      LAYER M4 ;
        RECT  290.725 429.504 291.564 429.528 ;
        RECT  291.516 429.504 291.6 429.528 ;
    END
  END wd[241]
  PIN wd[242]
    DIRECTION INPUT ;
    USE SIGNAL ;
    PORT
      LAYER M4 ;
        RECT  290.725 430.32 291.564 430.344 ;
        RECT  291.516 430.32 291.6 430.344 ;
    END
  END wd[242]
  PIN wd[243]
    DIRECTION INPUT ;
    USE SIGNAL ;
    PORT
      LAYER M4 ;
        RECT  290.725 431.136 291.564 431.16 ;
        RECT  291.516 431.136 291.6 431.16 ;
    END
  END wd[243]
  PIN wd[244]
    DIRECTION INPUT ;
    USE SIGNAL ;
    PORT
      LAYER M4 ;
        RECT  290.725 431.904 291.564 431.928 ;
        RECT  291.516 431.904 291.6 431.928 ;
    END
  END wd[244]
  PIN wd[245]
    DIRECTION INPUT ;
    USE SIGNAL ;
    PORT
      LAYER M4 ;
        RECT  290.725 432.72 291.564 432.744 ;
        RECT  291.516 432.72 291.6 432.744 ;
    END
  END wd[245]
  PIN wd[246]
    DIRECTION INPUT ;
    USE SIGNAL ;
    PORT
      LAYER M4 ;
        RECT  290.725 433.536 291.564 433.56 ;
        RECT  291.516 433.536 291.6 433.56 ;
    END
  END wd[246]
  PIN wd[247]
    DIRECTION INPUT ;
    USE SIGNAL ;
    PORT
      LAYER M4 ;
        RECT  290.725 434.352 291.564 434.376 ;
        RECT  291.516 434.352 291.6 434.376 ;
    END
  END wd[247]
  PIN wd[248]
    DIRECTION INPUT ;
    USE SIGNAL ;
    PORT
      LAYER M4 ;
        RECT  290.725 435.168 291.564 435.192 ;
        RECT  291.516 435.168 291.6 435.192 ;
    END
  END wd[248]
  PIN wd[249]
    DIRECTION INPUT ;
    USE SIGNAL ;
    PORT
      LAYER M4 ;
        RECT  290.725 435.984 291.564 436.008 ;
        RECT  291.516 435.984 291.6 436.008 ;
    END
  END wd[249]
  PIN wd[24]
    DIRECTION INPUT ;
    USE SIGNAL ;
    PORT
      LAYER M4 ;
        RECT  290.725 253.68 291.564 253.704 ;
        RECT  291.516 253.68 291.6 253.704 ;
    END
  END wd[24]
  PIN wd[250]
    DIRECTION INPUT ;
    USE SIGNAL ;
    PORT
      LAYER M4 ;
        RECT  290.725 436.8 291.564 436.824 ;
        RECT  291.516 436.8 291.6 436.824 ;
    END
  END wd[250]
  PIN wd[251]
    DIRECTION INPUT ;
    USE SIGNAL ;
    PORT
      LAYER M4 ;
        RECT  290.725 437.616 291.564 437.64 ;
        RECT  291.516 437.616 291.6 437.64 ;
    END
  END wd[251]
  PIN wd[252]
    DIRECTION INPUT ;
    USE SIGNAL ;
    PORT
      LAYER M4 ;
        RECT  290.725 438.432 291.564 438.456 ;
        RECT  291.516 438.432 291.6 438.456 ;
    END
  END wd[252]
  PIN wd[253]
    DIRECTION INPUT ;
    USE SIGNAL ;
    PORT
      LAYER M4 ;
        RECT  290.725 439.248 291.564 439.272 ;
        RECT  291.516 439.248 291.6 439.272 ;
    END
  END wd[253]
  PIN wd[254]
    DIRECTION INPUT ;
    USE SIGNAL ;
    PORT
      LAYER M4 ;
        RECT  290.725 440.016 291.564 440.04 ;
        RECT  291.516 440.016 291.6 440.04 ;
    END
  END wd[254]
  PIN wd[255]
    DIRECTION INPUT ;
    USE SIGNAL ;
    PORT
      LAYER M4 ;
        RECT  290.725 440.832 291.564 440.856 ;
        RECT  291.516 440.832 291.6 440.856 ;
    END
  END wd[255]
  PIN wd[25]
    DIRECTION INPUT ;
    USE SIGNAL ;
    PORT
      LAYER M4 ;
        RECT  290.725 254.448 291.564 254.472 ;
        RECT  291.516 254.448 291.6 254.472 ;
    END
  END wd[25]
  PIN wd[26]
    DIRECTION INPUT ;
    USE SIGNAL ;
    PORT
      LAYER M4 ;
        RECT  290.725 255.264 291.564 255.288 ;
        RECT  291.516 255.264 291.6 255.288 ;
    END
  END wd[26]
  PIN wd[27]
    DIRECTION INPUT ;
    USE SIGNAL ;
    PORT
      LAYER M4 ;
        RECT  290.725 256.08 291.564 256.104 ;
        RECT  291.516 256.08 291.6 256.104 ;
    END
  END wd[27]
  PIN wd[28]
    DIRECTION INPUT ;
    USE SIGNAL ;
    PORT
      LAYER M4 ;
        RECT  290.725 256.896 291.564 256.92 ;
        RECT  291.516 256.896 291.6 256.92 ;
    END
  END wd[28]
  PIN wd[29]
    DIRECTION INPUT ;
    USE SIGNAL ;
    PORT
      LAYER M4 ;
        RECT  290.725 257.712 291.564 257.736 ;
        RECT  291.516 257.712 291.6 257.736 ;
    END
  END wd[29]
  PIN wd[2]
    DIRECTION INPUT ;
    USE SIGNAL ;
    PORT
      LAYER M4 ;
        RECT  290.725 235.824 291.564 235.848 ;
        RECT  291.516 235.824 291.6 235.848 ;
    END
  END wd[2]
  PIN wd[30]
    DIRECTION INPUT ;
    USE SIGNAL ;
    PORT
      LAYER M4 ;
        RECT  290.725 258.528 291.564 258.552 ;
        RECT  291.516 258.528 291.6 258.552 ;
    END
  END wd[30]
  PIN wd[31]
    DIRECTION INPUT ;
    USE SIGNAL ;
    PORT
      LAYER M4 ;
        RECT  290.725 259.344 291.564 259.368 ;
        RECT  291.516 259.344 291.6 259.368 ;
    END
  END wd[31]
  PIN wd[32]
    DIRECTION INPUT ;
    USE SIGNAL ;
    PORT
      LAYER M4 ;
        RECT  290.725 260.16 291.564 260.184 ;
        RECT  291.516 260.16 291.6 260.184 ;
    END
  END wd[32]
  PIN wd[33]
    DIRECTION INPUT ;
    USE SIGNAL ;
    PORT
      LAYER M4 ;
        RECT  290.725 260.976 291.564 261 ;
        RECT  291.516 260.976 291.6 261 ;
    END
  END wd[33]
  PIN wd[34]
    DIRECTION INPUT ;
    USE SIGNAL ;
    PORT
      LAYER M4 ;
        RECT  290.725 261.792 291.564 261.816 ;
        RECT  291.516 261.792 291.6 261.816 ;
    END
  END wd[34]
  PIN wd[35]
    DIRECTION INPUT ;
    USE SIGNAL ;
    PORT
      LAYER M4 ;
        RECT  290.725 262.608 291.564 262.632 ;
        RECT  291.516 262.608 291.6 262.632 ;
    END
  END wd[35]
  PIN wd[36]
    DIRECTION INPUT ;
    USE SIGNAL ;
    PORT
      LAYER M4 ;
        RECT  290.725 263.376 291.564 263.4 ;
        RECT  291.516 263.376 291.6 263.4 ;
    END
  END wd[36]
  PIN wd[37]
    DIRECTION INPUT ;
    USE SIGNAL ;
    PORT
      LAYER M4 ;
        RECT  290.725 264.192 291.564 264.216 ;
        RECT  291.516 264.192 291.6 264.216 ;
    END
  END wd[37]
  PIN wd[38]
    DIRECTION INPUT ;
    USE SIGNAL ;
    PORT
      LAYER M4 ;
        RECT  290.725 265.008 291.564 265.032 ;
        RECT  291.516 265.008 291.6 265.032 ;
    END
  END wd[38]
  PIN wd[39]
    DIRECTION INPUT ;
    USE SIGNAL ;
    PORT
      LAYER M4 ;
        RECT  290.725 265.824 291.564 265.848 ;
        RECT  291.516 265.824 291.6 265.848 ;
    END
  END wd[39]
  PIN wd[3]
    DIRECTION INPUT ;
    USE SIGNAL ;
    PORT
      LAYER M4 ;
        RECT  290.725 236.64 291.564 236.664 ;
        RECT  291.516 236.64 291.6 236.664 ;
    END
  END wd[3]
  PIN wd[40]
    DIRECTION INPUT ;
    USE SIGNAL ;
    PORT
      LAYER M4 ;
        RECT  290.725 266.64 291.564 266.664 ;
        RECT  291.516 266.64 291.6 266.664 ;
    END
  END wd[40]
  PIN wd[41]
    DIRECTION INPUT ;
    USE SIGNAL ;
    PORT
      LAYER M4 ;
        RECT  290.725 267.456 291.564 267.48 ;
        RECT  291.516 267.456 291.6 267.48 ;
    END
  END wd[41]
  PIN wd[42]
    DIRECTION INPUT ;
    USE SIGNAL ;
    PORT
      LAYER M4 ;
        RECT  290.725 268.272 291.564 268.296 ;
        RECT  291.516 268.272 291.6 268.296 ;
    END
  END wd[42]
  PIN wd[43]
    DIRECTION INPUT ;
    USE SIGNAL ;
    PORT
      LAYER M4 ;
        RECT  290.725 269.088 291.564 269.112 ;
        RECT  291.516 269.088 291.6 269.112 ;
    END
  END wd[43]
  PIN wd[44]
    DIRECTION INPUT ;
    USE SIGNAL ;
    PORT
      LAYER M4 ;
        RECT  290.725 269.904 291.564 269.928 ;
        RECT  291.516 269.904 291.6 269.928 ;
    END
  END wd[44]
  PIN wd[45]
    DIRECTION INPUT ;
    USE SIGNAL ;
    PORT
      LAYER M4 ;
        RECT  290.725 270.72 291.564 270.744 ;
        RECT  291.516 270.72 291.6 270.744 ;
    END
  END wd[45]
  PIN wd[46]
    DIRECTION INPUT ;
    USE SIGNAL ;
    PORT
      LAYER M4 ;
        RECT  290.725 271.536 291.564 271.56 ;
        RECT  291.516 271.536 291.6 271.56 ;
    END
  END wd[46]
  PIN wd[47]
    DIRECTION INPUT ;
    USE SIGNAL ;
    PORT
      LAYER M4 ;
        RECT  290.725 272.304 291.564 272.328 ;
        RECT  291.516 272.304 291.6 272.328 ;
    END
  END wd[47]
  PIN wd[48]
    DIRECTION INPUT ;
    USE SIGNAL ;
    PORT
      LAYER M4 ;
        RECT  290.725 273.12 291.564 273.144 ;
        RECT  291.516 273.12 291.6 273.144 ;
    END
  END wd[48]
  PIN wd[49]
    DIRECTION INPUT ;
    USE SIGNAL ;
    PORT
      LAYER M4 ;
        RECT  290.725 273.936 291.564 273.96 ;
        RECT  291.516 273.936 291.6 273.96 ;
    END
  END wd[49]
  PIN wd[4]
    DIRECTION INPUT ;
    USE SIGNAL ;
    PORT
      LAYER M4 ;
        RECT  290.725 237.456 291.564 237.48 ;
        RECT  291.516 237.456 291.6 237.48 ;
    END
  END wd[4]
  PIN wd[50]
    DIRECTION INPUT ;
    USE SIGNAL ;
    PORT
      LAYER M4 ;
        RECT  290.725 274.704 291.564 274.728 ;
        RECT  291.516 274.704 291.6 274.728 ;
    END
  END wd[50]
  PIN wd[51]
    DIRECTION INPUT ;
    USE SIGNAL ;
    PORT
      LAYER M4 ;
        RECT  290.725 275.52 291.564 275.544 ;
        RECT  291.516 275.52 291.6 275.544 ;
    END
  END wd[51]
  PIN wd[52]
    DIRECTION INPUT ;
    USE SIGNAL ;
    PORT
      LAYER M4 ;
        RECT  290.725 276.336 291.564 276.36 ;
        RECT  291.516 276.336 291.6 276.36 ;
    END
  END wd[52]
  PIN wd[53]
    DIRECTION INPUT ;
    USE SIGNAL ;
    PORT
      LAYER M4 ;
        RECT  290.725 277.152 291.564 277.176 ;
        RECT  291.516 277.152 291.6 277.176 ;
    END
  END wd[53]
  PIN wd[54]
    DIRECTION INPUT ;
    USE SIGNAL ;
    PORT
      LAYER M4 ;
        RECT  290.725 277.968 291.564 277.992 ;
        RECT  291.516 277.968 291.6 277.992 ;
    END
  END wd[54]
  PIN wd[55]
    DIRECTION INPUT ;
    USE SIGNAL ;
    PORT
      LAYER M4 ;
        RECT  290.725 278.784 291.564 278.808 ;
        RECT  291.516 278.784 291.6 278.808 ;
    END
  END wd[55]
  PIN wd[56]
    DIRECTION INPUT ;
    USE SIGNAL ;
    PORT
      LAYER M4 ;
        RECT  290.725 279.6 291.564 279.624 ;
        RECT  291.516 279.6 291.6 279.624 ;
    END
  END wd[56]
  PIN wd[57]
    DIRECTION INPUT ;
    USE SIGNAL ;
    PORT
      LAYER M4 ;
        RECT  290.725 280.416 291.564 280.44 ;
        RECT  291.516 280.416 291.6 280.44 ;
    END
  END wd[57]
  PIN wd[58]
    DIRECTION INPUT ;
    USE SIGNAL ;
    PORT
      LAYER M4 ;
        RECT  290.725 281.232 291.564 281.256 ;
        RECT  291.516 281.232 291.6 281.256 ;
    END
  END wd[58]
  PIN wd[59]
    DIRECTION INPUT ;
    USE SIGNAL ;
    PORT
      LAYER M4 ;
        RECT  290.725 282 291.564 282.024 ;
        RECT  291.516 282 291.6 282.024 ;
    END
  END wd[59]
  PIN wd[5]
    DIRECTION INPUT ;
    USE SIGNAL ;
    PORT
      LAYER M4 ;
        RECT  290.725 238.272 291.564 238.296 ;
        RECT  291.516 238.272 291.6 238.296 ;
    END
  END wd[5]
  PIN wd[60]
    DIRECTION INPUT ;
    USE SIGNAL ;
    PORT
      LAYER M4 ;
        RECT  290.725 282.816 291.564 282.84 ;
        RECT  291.516 282.816 291.6 282.84 ;
    END
  END wd[60]
  PIN wd[61]
    DIRECTION INPUT ;
    USE SIGNAL ;
    PORT
      LAYER M4 ;
        RECT  290.725 283.632 291.564 283.656 ;
        RECT  291.516 283.632 291.6 283.656 ;
    END
  END wd[61]
  PIN wd[62]
    DIRECTION INPUT ;
    USE SIGNAL ;
    PORT
      LAYER M4 ;
        RECT  290.725 284.448 291.564 284.472 ;
        RECT  291.516 284.448 291.6 284.472 ;
    END
  END wd[62]
  PIN wd[63]
    DIRECTION INPUT ;
    USE SIGNAL ;
    PORT
      LAYER M4 ;
        RECT  290.725 285.264 291.564 285.288 ;
        RECT  291.516 285.264 291.6 285.288 ;
    END
  END wd[63]
  PIN wd[64]
    DIRECTION INPUT ;
    USE SIGNAL ;
    PORT
      LAYER M4 ;
        RECT  290.725 286.08 291.564 286.104 ;
        RECT  291.516 286.08 291.6 286.104 ;
    END
  END wd[64]
  PIN wd[65]
    DIRECTION INPUT ;
    USE SIGNAL ;
    PORT
      LAYER M4 ;
        RECT  290.725 286.896 291.564 286.92 ;
        RECT  291.516 286.896 291.6 286.92 ;
    END
  END wd[65]
  PIN wd[66]
    DIRECTION INPUT ;
    USE SIGNAL ;
    PORT
      LAYER M4 ;
        RECT  290.725 287.712 291.564 287.736 ;
        RECT  291.516 287.712 291.6 287.736 ;
    END
  END wd[66]
  PIN wd[67]
    DIRECTION INPUT ;
    USE SIGNAL ;
    PORT
      LAYER M4 ;
        RECT  290.725 288.528 291.564 288.552 ;
        RECT  291.516 288.528 291.6 288.552 ;
    END
  END wd[67]
  PIN wd[68]
    DIRECTION INPUT ;
    USE SIGNAL ;
    PORT
      LAYER M4 ;
        RECT  290.725 289.344 291.564 289.368 ;
        RECT  291.516 289.344 291.6 289.368 ;
    END
  END wd[68]
  PIN wd[69]
    DIRECTION INPUT ;
    USE SIGNAL ;
    PORT
      LAYER M4 ;
        RECT  290.725 290.16 291.564 290.184 ;
        RECT  291.516 290.16 291.6 290.184 ;
    END
  END wd[69]
  PIN wd[6]
    DIRECTION INPUT ;
    USE SIGNAL ;
    PORT
      LAYER M4 ;
        RECT  290.725 239.088 291.564 239.112 ;
        RECT  291.516 239.088 291.6 239.112 ;
    END
  END wd[6]
  PIN wd[70]
    DIRECTION INPUT ;
    USE SIGNAL ;
    PORT
      LAYER M4 ;
        RECT  290.725 290.928 291.564 290.952 ;
        RECT  291.516 290.928 291.6 290.952 ;
    END
  END wd[70]
  PIN wd[71]
    DIRECTION INPUT ;
    USE SIGNAL ;
    PORT
      LAYER M4 ;
        RECT  290.725 291.744 291.564 291.768 ;
        RECT  291.516 291.744 291.6 291.768 ;
    END
  END wd[71]
  PIN wd[72]
    DIRECTION INPUT ;
    USE SIGNAL ;
    PORT
      LAYER M4 ;
        RECT  290.725 292.56 291.564 292.584 ;
        RECT  291.516 292.56 291.6 292.584 ;
    END
  END wd[72]
  PIN wd[73]
    DIRECTION INPUT ;
    USE SIGNAL ;
    PORT
      LAYER M4 ;
        RECT  290.725 293.376 291.564 293.4 ;
        RECT  291.516 293.376 291.6 293.4 ;
    END
  END wd[73]
  PIN wd[74]
    DIRECTION INPUT ;
    USE SIGNAL ;
    PORT
      LAYER M4 ;
        RECT  290.725 294.192 291.564 294.216 ;
        RECT  291.516 294.192 291.6 294.216 ;
    END
  END wd[74]
  PIN wd[75]
    DIRECTION INPUT ;
    USE SIGNAL ;
    PORT
      LAYER M4 ;
        RECT  290.725 295.008 291.564 295.032 ;
        RECT  291.516 295.008 291.6 295.032 ;
    END
  END wd[75]
  PIN wd[76]
    DIRECTION INPUT ;
    USE SIGNAL ;
    PORT
      LAYER M4 ;
        RECT  290.725 295.824 291.564 295.848 ;
        RECT  291.516 295.824 291.6 295.848 ;
    END
  END wd[76]
  PIN wd[77]
    DIRECTION INPUT ;
    USE SIGNAL ;
    PORT
      LAYER M4 ;
        RECT  290.725 296.64 291.564 296.664 ;
        RECT  291.516 296.64 291.6 296.664 ;
    END
  END wd[77]
  PIN wd[78]
    DIRECTION INPUT ;
    USE SIGNAL ;
    PORT
      LAYER M4 ;
        RECT  290.725 297.456 291.564 297.48 ;
        RECT  291.516 297.456 291.6 297.48 ;
    END
  END wd[78]
  PIN wd[79]
    DIRECTION INPUT ;
    USE SIGNAL ;
    PORT
      LAYER M4 ;
        RECT  290.725 298.272 291.564 298.296 ;
        RECT  291.516 298.272 291.6 298.296 ;
    END
  END wd[79]
  PIN wd[7]
    DIRECTION INPUT ;
    USE SIGNAL ;
    PORT
      LAYER M4 ;
        RECT  290.725 239.904 291.564 239.928 ;
        RECT  291.516 239.904 291.6 239.928 ;
    END
  END wd[7]
  PIN wd[80]
    DIRECTION INPUT ;
    USE SIGNAL ;
    PORT
      LAYER M4 ;
        RECT  290.725 299.088 291.564 299.112 ;
        RECT  291.516 299.088 291.6 299.112 ;
    END
  END wd[80]
  PIN wd[81]
    DIRECTION INPUT ;
    USE SIGNAL ;
    PORT
      LAYER M4 ;
        RECT  290.725 299.856 291.564 299.88 ;
        RECT  291.516 299.856 291.6 299.88 ;
    END
  END wd[81]
  PIN wd[82]
    DIRECTION INPUT ;
    USE SIGNAL ;
    PORT
      LAYER M4 ;
        RECT  290.725 300.672 291.564 300.696 ;
        RECT  291.516 300.672 291.6 300.696 ;
    END
  END wd[82]
  PIN wd[83]
    DIRECTION INPUT ;
    USE SIGNAL ;
    PORT
      LAYER M4 ;
        RECT  290.725 301.44 291.564 301.464 ;
        RECT  291.516 301.44 291.6 301.464 ;
    END
  END wd[83]
  PIN wd[84]
    DIRECTION INPUT ;
    USE SIGNAL ;
    PORT
      LAYER M4 ;
        RECT  290.725 302.256 291.564 302.28 ;
        RECT  291.516 302.256 291.6 302.28 ;
    END
  END wd[84]
  PIN wd[85]
    DIRECTION INPUT ;
    USE SIGNAL ;
    PORT
      LAYER M4 ;
        RECT  290.725 303.072 291.564 303.096 ;
        RECT  291.516 303.072 291.6 303.096 ;
    END
  END wd[85]
  PIN wd[86]
    DIRECTION INPUT ;
    USE SIGNAL ;
    PORT
      LAYER M4 ;
        RECT  290.725 303.888 291.564 303.912 ;
        RECT  291.516 303.888 291.6 303.912 ;
    END
  END wd[86]
  PIN wd[87]
    DIRECTION INPUT ;
    USE SIGNAL ;
    PORT
      LAYER M4 ;
        RECT  290.725 304.704 291.564 304.728 ;
        RECT  291.516 304.704 291.6 304.728 ;
    END
  END wd[87]
  PIN wd[88]
    DIRECTION INPUT ;
    USE SIGNAL ;
    PORT
      LAYER M4 ;
        RECT  290.725 305.52 291.564 305.544 ;
        RECT  291.516 305.52 291.6 305.544 ;
    END
  END wd[88]
  PIN wd[89]
    DIRECTION INPUT ;
    USE SIGNAL ;
    PORT
      LAYER M4 ;
        RECT  290.725 306.336 291.564 306.36 ;
        RECT  291.516 306.336 291.6 306.36 ;
    END
  END wd[89]
  PIN wd[8]
    DIRECTION INPUT ;
    USE SIGNAL ;
    PORT
      LAYER M4 ;
        RECT  290.725 240.72 291.564 240.744 ;
        RECT  291.516 240.72 291.6 240.744 ;
    END
  END wd[8]
  PIN wd[90]
    DIRECTION INPUT ;
    USE SIGNAL ;
    PORT
      LAYER M4 ;
        RECT  290.725 307.152 291.564 307.176 ;
        RECT  291.516 307.152 291.6 307.176 ;
    END
  END wd[90]
  PIN wd[91]
    DIRECTION INPUT ;
    USE SIGNAL ;
    PORT
      LAYER M4 ;
        RECT  290.725 307.968 291.564 307.992 ;
        RECT  291.516 307.968 291.6 307.992 ;
    END
  END wd[91]
  PIN wd[92]
    DIRECTION INPUT ;
    USE SIGNAL ;
    PORT
      LAYER M4 ;
        RECT  290.725 308.784 291.564 308.808 ;
        RECT  291.516 308.784 291.6 308.808 ;
    END
  END wd[92]
  PIN wd[93]
    DIRECTION INPUT ;
    USE SIGNAL ;
    PORT
      LAYER M4 ;
        RECT  290.725 309.6 291.564 309.624 ;
        RECT  291.516 309.6 291.6 309.624 ;
    END
  END wd[93]
  PIN wd[94]
    DIRECTION INPUT ;
    USE SIGNAL ;
    PORT
      LAYER M4 ;
        RECT  290.725 310.368 291.564 310.392 ;
        RECT  291.516 310.368 291.6 310.392 ;
    END
  END wd[94]
  PIN wd[95]
    DIRECTION INPUT ;
    USE SIGNAL ;
    PORT
      LAYER M4 ;
        RECT  290.725 311.184 291.564 311.208 ;
        RECT  291.516 311.184 291.6 311.208 ;
    END
  END wd[95]
  PIN wd[96]
    DIRECTION INPUT ;
    USE SIGNAL ;
    PORT
      LAYER M4 ;
        RECT  290.725 312 291.564 312.024 ;
        RECT  291.516 312 291.6 312.024 ;
    END
  END wd[96]
  PIN wd[97]
    DIRECTION INPUT ;
    USE SIGNAL ;
    PORT
      LAYER M4 ;
        RECT  290.725 312.816 291.564 312.84 ;
        RECT  291.516 312.816 291.6 312.84 ;
    END
  END wd[97]
  PIN wd[98]
    DIRECTION INPUT ;
    USE SIGNAL ;
    PORT
      LAYER M4 ;
        RECT  290.725 313.632 291.564 313.656 ;
        RECT  291.516 313.632 291.6 313.656 ;
    END
  END wd[98]
  PIN wd[99]
    DIRECTION INPUT ;
    USE SIGNAL ;
    PORT
      LAYER M4 ;
        RECT  290.725 314.448 291.564 314.472 ;
        RECT  291.516 314.448 291.6 314.472 ;
    END
  END wd[99]
  PIN wd[9]
    DIRECTION INPUT ;
    USE SIGNAL ;
    PORT
      LAYER M4 ;
        RECT  290.725 241.536 291.564 241.56 ;
        RECT  291.516 241.536 291.6 241.56 ;
    END
  END wd[9]
  PIN we
    DIRECTION INPUT ;
    USE SIGNAL ;
    PORT
      LAYER M4 ;
        RECT  290.725 441.648 291.564 441.672 ;
        RECT  291.516 441.648 291.6 441.672 ;
    END
  END we
  PIN wm_next[0]
    DIRECTION INPUT ;
    USE SIGNAL ;
    PORT
      LAYER M4 ;
        RECT  290.725 442.464 291.564 442.488 ;
        RECT  291.516 442.464 291.6 442.488 ;
    END
  END wm_next[0]
  PIN wm_next[10]
    DIRECTION INPUT ;
    USE SIGNAL ;
    PORT
      LAYER M4 ;
        RECT  290.725 450.576 291.564 450.6 ;
        RECT  291.516 450.576 291.6 450.6 ;
    END
  END wm_next[10]
  PIN wm_next[11]
    DIRECTION INPUT ;
    USE SIGNAL ;
    PORT
      LAYER M4 ;
        RECT  290.725 451.392 291.564 451.416 ;
        RECT  291.516 451.392 291.6 451.416 ;
    END
  END wm_next[11]
  PIN wm_next[12]
    DIRECTION INPUT ;
    USE SIGNAL ;
    PORT
      LAYER M4 ;
        RECT  290.725 452.208 291.564 452.232 ;
        RECT  291.516 452.208 291.6 452.232 ;
    END
  END wm_next[12]
  PIN wm_next[13]
    DIRECTION INPUT ;
    USE SIGNAL ;
    PORT
      LAYER M4 ;
        RECT  290.725 453.024 291.564 453.048 ;
        RECT  291.516 453.024 291.6 453.048 ;
    END
  END wm_next[13]
  PIN wm_next[14]
    DIRECTION INPUT ;
    USE SIGNAL ;
    PORT
      LAYER M4 ;
        RECT  290.725 453.792 291.564 453.816 ;
        RECT  291.516 453.792 291.6 453.816 ;
    END
  END wm_next[14]
  PIN wm_next[15]
    DIRECTION INPUT ;
    USE SIGNAL ;
    PORT
      LAYER M4 ;
        RECT  290.725 454.608 291.564 454.632 ;
        RECT  291.516 454.608 291.6 454.632 ;
    END
  END wm_next[15]
  PIN wm_next[1]
    DIRECTION INPUT ;
    USE SIGNAL ;
    PORT
      LAYER M4 ;
        RECT  290.725 443.28 291.564 443.304 ;
        RECT  291.516 443.28 291.6 443.304 ;
    END
  END wm_next[1]
  PIN wm_next[2]
    DIRECTION INPUT ;
    USE SIGNAL ;
    PORT
      LAYER M4 ;
        RECT  290.725 444.096 291.564 444.12 ;
        RECT  291.516 444.096 291.6 444.12 ;
    END
  END wm_next[2]
  PIN wm_next[3]
    DIRECTION INPUT ;
    USE SIGNAL ;
    PORT
      LAYER M4 ;
        RECT  290.725 444.912 291.564 444.936 ;
        RECT  291.516 444.912 291.6 444.936 ;
    END
  END wm_next[3]
  PIN wm_next[4]
    DIRECTION INPUT ;
    USE SIGNAL ;
    PORT
      LAYER M4 ;
        RECT  290.725 445.728 291.564 445.752 ;
        RECT  291.516 445.728 291.6 445.752 ;
    END
  END wm_next[4]
  PIN wm_next[5]
    DIRECTION INPUT ;
    USE SIGNAL ;
    PORT
      LAYER M4 ;
        RECT  290.725 446.544 291.564 446.568 ;
        RECT  291.516 446.544 291.6 446.568 ;
    END
  END wm_next[5]
  PIN wm_next[6]
    DIRECTION INPUT ;
    USE SIGNAL ;
    PORT
      LAYER M4 ;
        RECT  290.725 447.36 291.564 447.384 ;
        RECT  291.516 447.36 291.6 447.384 ;
    END
  END wm_next[6]
  PIN wm_next[7]
    DIRECTION INPUT ;
    USE SIGNAL ;
    PORT
      LAYER M4 ;
        RECT  290.725 448.176 291.564 448.2 ;
        RECT  291.516 448.176 291.6 448.2 ;
    END
  END wm_next[7]
  PIN wm_next[8]
    DIRECTION INPUT ;
    USE SIGNAL ;
    PORT
      LAYER M4 ;
        RECT  290.725 448.944 291.564 448.968 ;
        RECT  291.516 448.944 291.6 448.968 ;
    END
  END wm_next[8]
  PIN wm_next[9]
    DIRECTION INPUT ;
    USE SIGNAL ;
    PORT
      LAYER M4 ;
        RECT  290.725 449.76 291.564 449.784 ;
        RECT  291.516 449.76 291.6 449.784 ;
    END
  END wm_next[9]
  PIN VDD
    DIRECTION INOUT ;
    USE POWER ;
    PORT
      LAYER M5 ;
        RECT  282.996 4.311 283.116 455.229 ;
        RECT  278.676 4.311 278.796 455.229 ;
        RECT  274.356 4.311 274.476 455.229 ;
        RECT  270.036 4.311 270.156 455.229 ;
        RECT  265.716 4.311 265.836 455.229 ;
        RECT  261.396 4.311 261.516 455.229 ;
        RECT  257.076 4.311 257.196 455.229 ;
        RECT  252.756 4.311 252.876 455.229 ;
        RECT  248.436 4.311 248.556 455.229 ;
        RECT  244.116 4.311 244.236 455.229 ;
        RECT  239.796 4.311 239.916 455.229 ;
        RECT  235.476 4.311 235.596 455.229 ;
        RECT  231.156 4.311 231.276 455.229 ;
        RECT  226.836 4.311 226.956 455.229 ;
        RECT  222.516 4.311 222.636 455.229 ;
        RECT  218.196 4.311 218.316 455.229 ;
        RECT  213.876 4.311 213.996 455.229 ;
        RECT  209.556 4.311 209.676 455.229 ;
        RECT  205.236 4.311 205.356 455.229 ;
        RECT  200.916 4.311 201.036 455.229 ;
        RECT  196.596 4.311 196.716 455.229 ;
        RECT  192.276 4.311 192.396 455.229 ;
        RECT  187.956 4.311 188.076 455.229 ;
        RECT  183.636 4.311 183.756 455.229 ;
        RECT  179.316 4.311 179.436 455.229 ;
        RECT  174.996 4.311 175.116 455.229 ;
        RECT  170.676 4.311 170.796 455.229 ;
        RECT  166.356 4.311 166.476 455.229 ;
        RECT  162.036 4.311 162.156 455.229 ;
        RECT  157.716 4.311 157.836 455.229 ;
        RECT  153.396 4.311 153.516 455.229 ;
        RECT  149.076 4.311 149.196 455.229 ;
        RECT  144.756 4.311 144.876 455.229 ;
        RECT  140.436 4.311 140.556 455.229 ;
        RECT  136.116 4.311 136.236 455.229 ;
        RECT  131.796 4.311 131.916 455.229 ;
        RECT  127.476 4.311 127.596 455.229 ;
        RECT  123.156 4.311 123.276 455.229 ;
        RECT  118.836 4.311 118.956 455.229 ;
        RECT  114.516 4.311 114.636 455.229 ;
        RECT  110.196 4.311 110.316 455.229 ;
        RECT  105.876 4.311 105.996 455.229 ;
        RECT  101.556 4.311 101.676 455.229 ;
        RECT  97.236 4.311 97.356 455.229 ;
        RECT  92.916 4.311 93.036 455.229 ;
        RECT  88.596 4.311 88.716 455.229 ;
        RECT  84.276 4.311 84.396 455.229 ;
        RECT  79.956 4.311 80.076 455.229 ;
        RECT  75.636 4.311 75.756 455.229 ;
        RECT  71.316 4.311 71.436 455.229 ;
        RECT  66.996 4.311 67.116 455.229 ;
        RECT  62.676 4.311 62.796 455.229 ;
        RECT  58.356 4.311 58.476 455.229 ;
        RECT  54.036 4.311 54.156 455.229 ;
        RECT  49.716 4.311 49.836 455.229 ;
        RECT  45.396 4.311 45.516 455.229 ;
        RECT  41.076 4.311 41.196 455.229 ;
        RECT  36.756 4.311 36.876 455.229 ;
        RECT  32.436 4.311 32.556 455.229 ;
        RECT  28.116 4.311 28.236 455.229 ;
        RECT  23.796 4.311 23.916 455.229 ;
        RECT  19.476 4.311 19.596 455.229 ;
        RECT  15.156 4.311 15.276 455.229 ;
        RECT  10.836 4.311 10.956 455.229 ;
        RECT  6.516 4.311 6.636 455.229 ;
    END
  END VDD
  PIN VSS
    DIRECTION INOUT ;
    USE GROUND ;
    PORT
      LAYER M5 ;
        RECT  287.124 4.297 287.244 455.243 ;
        RECT  282.804 4.297 282.924 455.243 ;
        RECT  278.484 4.297 278.604 455.243 ;
        RECT  274.164 4.297 274.284 455.243 ;
        RECT  269.844 4.297 269.964 455.243 ;
        RECT  265.524 4.297 265.644 455.243 ;
        RECT  261.204 4.297 261.324 455.243 ;
        RECT  256.884 4.297 257.004 455.243 ;
        RECT  252.564 4.297 252.684 455.243 ;
        RECT  248.244 4.297 248.364 455.243 ;
        RECT  243.924 4.297 244.044 455.243 ;
        RECT  239.604 4.297 239.724 455.243 ;
        RECT  235.284 4.297 235.404 455.243 ;
        RECT  230.964 4.297 231.084 455.243 ;
        RECT  226.644 4.311 226.764 455.229 ;
        RECT  222.324 4.311 222.444 455.229 ;
        RECT  218.004 4.311 218.124 455.229 ;
        RECT  213.684 4.311 213.804 455.229 ;
        RECT  209.364 4.311 209.484 455.229 ;
        RECT  205.044 4.311 205.164 455.229 ;
        RECT  200.724 4.311 200.844 455.229 ;
        RECT  196.404 4.311 196.524 455.229 ;
        RECT  192.084 4.311 192.204 455.229 ;
        RECT  187.764 4.311 187.884 455.229 ;
        RECT  183.444 4.311 183.564 455.229 ;
        RECT  179.124 4.311 179.244 455.229 ;
        RECT  174.804 4.311 174.924 455.229 ;
        RECT  170.484 4.311 170.604 455.229 ;
        RECT  166.164 4.311 166.284 455.229 ;
        RECT  161.844 4.311 161.964 455.229 ;
        RECT  157.524 4.311 157.644 455.229 ;
        RECT  153.204 4.311 153.324 455.229 ;
        RECT  148.884 4.311 149.004 455.229 ;
        RECT  144.564 4.311 144.684 455.229 ;
        RECT  140.244 4.311 140.364 455.229 ;
        RECT  135.924 4.311 136.044 455.229 ;
        RECT  131.604 4.311 131.724 455.229 ;
        RECT  127.284 4.311 127.404 455.229 ;
        RECT  122.964 4.311 123.084 455.229 ;
        RECT  118.644 4.311 118.764 455.229 ;
        RECT  114.324 4.311 114.444 455.229 ;
        RECT  110.004 4.311 110.124 455.229 ;
        RECT  105.684 4.311 105.804 455.229 ;
        RECT  101.364 4.311 101.484 455.229 ;
        RECT  97.044 4.311 97.164 455.229 ;
        RECT  92.724 4.311 92.844 455.229 ;
        RECT  88.404 4.311 88.524 455.229 ;
        RECT  84.084 4.311 84.204 455.229 ;
        RECT  79.764 4.311 79.884 455.229 ;
        RECT  75.444 4.311 75.564 455.229 ;
        RECT  71.124 4.311 71.244 455.229 ;
        RECT  66.804 4.311 66.924 455.229 ;
        RECT  62.484 4.311 62.604 455.229 ;
        RECT  58.164 4.311 58.284 455.229 ;
        RECT  53.844 4.311 53.964 455.229 ;
        RECT  49.524 4.311 49.644 455.229 ;
        RECT  45.204 4.297 45.324 455.243 ;
        RECT  40.884 4.297 41.004 455.243 ;
        RECT  36.564 4.297 36.684 455.243 ;
        RECT  32.244 4.297 32.364 455.243 ;
        RECT  27.924 4.297 28.044 455.243 ;
        RECT  23.604 4.297 23.724 455.243 ;
        RECT  19.284 4.297 19.404 455.243 ;
        RECT  14.964 4.297 15.084 455.243 ;
        RECT  10.644 4.297 10.764 455.243 ;
        RECT  6.324 4.297 6.444 455.243 ;
    END
  END VSS
  OBS
    LAYER RVTN ;
     RECT  0 4.261 291.6 455.243 ;
    LAYER RVTP ;
     RECT  0 4.261 291.6 455.243 ;
    LAYER M1 ;
     RECT  0 4.261 291.6 455.243 ;
    LAYER M2 ;
     RECT  0 4.261 291.6 455.243 ;
    LAYER M3 ;
     RECT  0 4.261 291.6 455.243 ;
    LAYER M4 ;
     RECT  0 4.261 291.6 455.243 ;
    LAYER M5 ;
     RECT  0 4.261 291.6 455.243 ;
  END
END dsdv_idx_txm_grp
END LIBRARY
